VERSION 5.7 ;
BUSBITCHARS "[]" ;
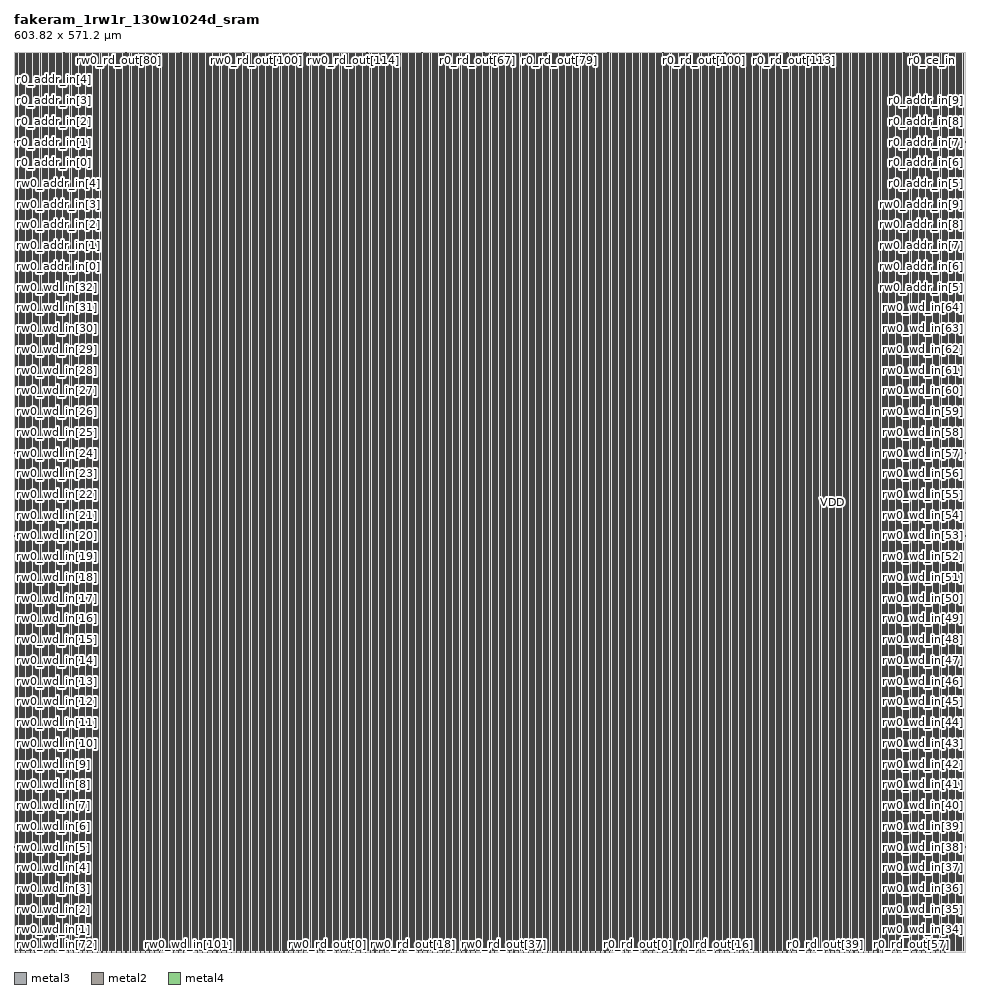
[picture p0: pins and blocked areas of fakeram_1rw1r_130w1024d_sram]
MACRO fakeram_1rw1r_130w1024d_sram
  FOREIGN fakeram_1rw1r_130w1024d_sram 0 0 ;
  SYMMETRY X Y R90 ;
  SIZE 603.820 BY 571.200 ;
  CLASS BLOCK ;
  PIN rw0_wd_in[0]
    DIRECTION INPUT ;
    USE SIGNAL ;
    SHAPE ABUTMENT ;
    PORT
      LAYER metal3 ;
      RECT 0.000 0.805 0.210 0.875 ;
    END
  END rw0_wd_in[0]
  PIN rw0_wd_in[1]
    DIRECTION INPUT ;
    USE SIGNAL ;
    SHAPE ABUTMENT ;
    PORT
      LAYER metal3 ;
      RECT 0.000 13.965 0.210 14.035 ;
    END
  END rw0_wd_in[1]
  PIN rw0_wd_in[2]
    DIRECTION INPUT ;
    USE SIGNAL ;
    SHAPE ABUTMENT ;
    PORT
      LAYER metal3 ;
      RECT 0.000 27.125 0.210 27.195 ;
    END
  END rw0_wd_in[2]
  PIN rw0_wd_in[3]
    DIRECTION INPUT ;
    USE SIGNAL ;
    SHAPE ABUTMENT ;
    PORT
      LAYER metal3 ;
      RECT 0.000 40.285 0.210 40.355 ;
    END
  END rw0_wd_in[3]
  PIN rw0_wd_in[4]
    DIRECTION INPUT ;
    USE SIGNAL ;
    SHAPE ABUTMENT ;
    PORT
      LAYER metal3 ;
      RECT 0.000 53.445 0.210 53.515 ;
    END
  END rw0_wd_in[4]
  PIN rw0_wd_in[5]
    DIRECTION INPUT ;
    USE SIGNAL ;
    SHAPE ABUTMENT ;
    PORT
      LAYER metal3 ;
      RECT 0.000 66.605 0.210 66.675 ;
    END
  END rw0_wd_in[5]
  PIN rw0_wd_in[6]
    DIRECTION INPUT ;
    USE SIGNAL ;
    SHAPE ABUTMENT ;
    PORT
      LAYER metal3 ;
      RECT 0.000 79.765 0.210 79.835 ;
    END
  END rw0_wd_in[6]
  PIN rw0_wd_in[7]
    DIRECTION INPUT ;
    USE SIGNAL ;
    SHAPE ABUTMENT ;
    PORT
      LAYER metal3 ;
      RECT 0.000 92.925 0.210 92.995 ;
    END
  END rw0_wd_in[7]
  PIN rw0_wd_in[8]
    DIRECTION INPUT ;
    USE SIGNAL ;
    SHAPE ABUTMENT ;
    PORT
      LAYER metal3 ;
      RECT 0.000 106.085 0.210 106.155 ;
    END
  END rw0_wd_in[8]
  PIN rw0_wd_in[9]
    DIRECTION INPUT ;
    USE SIGNAL ;
    SHAPE ABUTMENT ;
    PORT
      LAYER metal3 ;
      RECT 0.000 119.245 0.210 119.315 ;
    END
  END rw0_wd_in[9]
  PIN rw0_wd_in[10]
    DIRECTION INPUT ;
    USE SIGNAL ;
    SHAPE ABUTMENT ;
    PORT
      LAYER metal3 ;
      RECT 0.000 132.405 0.210 132.475 ;
    END
  END rw0_wd_in[10]
  PIN rw0_wd_in[11]
    DIRECTION INPUT ;
    USE SIGNAL ;
    SHAPE ABUTMENT ;
    PORT
      LAYER metal3 ;
      RECT 0.000 145.565 0.210 145.635 ;
    END
  END rw0_wd_in[11]
  PIN rw0_wd_in[12]
    DIRECTION INPUT ;
    USE SIGNAL ;
    SHAPE ABUTMENT ;
    PORT
      LAYER metal3 ;
      RECT 0.000 158.725 0.210 158.795 ;
    END
  END rw0_wd_in[12]
  PIN rw0_wd_in[13]
    DIRECTION INPUT ;
    USE SIGNAL ;
    SHAPE ABUTMENT ;
    PORT
      LAYER metal3 ;
      RECT 0.000 171.885 0.210 171.955 ;
    END
  END rw0_wd_in[13]
  PIN rw0_wd_in[14]
    DIRECTION INPUT ;
    USE SIGNAL ;
    SHAPE ABUTMENT ;
    PORT
      LAYER metal3 ;
      RECT 0.000 185.045 0.210 185.115 ;
    END
  END rw0_wd_in[14]
  PIN rw0_wd_in[15]
    DIRECTION INPUT ;
    USE SIGNAL ;
    SHAPE ABUTMENT ;
    PORT
      LAYER metal3 ;
      RECT 0.000 198.205 0.210 198.275 ;
    END
  END rw0_wd_in[15]
  PIN rw0_wd_in[16]
    DIRECTION INPUT ;
    USE SIGNAL ;
    SHAPE ABUTMENT ;
    PORT
      LAYER metal3 ;
      RECT 0.000 211.365 0.210 211.435 ;
    END
  END rw0_wd_in[16]
  PIN rw0_wd_in[17]
    DIRECTION INPUT ;
    USE SIGNAL ;
    SHAPE ABUTMENT ;
    PORT
      LAYER metal3 ;
      RECT 0.000 224.525 0.210 224.595 ;
    END
  END rw0_wd_in[17]
  PIN rw0_wd_in[18]
    DIRECTION INPUT ;
    USE SIGNAL ;
    SHAPE ABUTMENT ;
    PORT
      LAYER metal3 ;
      RECT 0.000 237.685 0.210 237.755 ;
    END
  END rw0_wd_in[18]
  PIN rw0_wd_in[19]
    DIRECTION INPUT ;
    USE SIGNAL ;
    SHAPE ABUTMENT ;
    PORT
      LAYER metal3 ;
      RECT 0.000 250.845 0.210 250.915 ;
    END
  END rw0_wd_in[19]
  PIN rw0_wd_in[20]
    DIRECTION INPUT ;
    USE SIGNAL ;
    SHAPE ABUTMENT ;
    PORT
      LAYER metal3 ;
      RECT 0.000 264.005 0.210 264.075 ;
    END
  END rw0_wd_in[20]
  PIN rw0_wd_in[21]
    DIRECTION INPUT ;
    USE SIGNAL ;
    SHAPE ABUTMENT ;
    PORT
      LAYER metal3 ;
      RECT 0.000 277.165 0.210 277.235 ;
    END
  END rw0_wd_in[21]
  PIN rw0_wd_in[22]
    DIRECTION INPUT ;
    USE SIGNAL ;
    SHAPE ABUTMENT ;
    PORT
      LAYER metal3 ;
      RECT 0.000 290.325 0.210 290.395 ;
    END
  END rw0_wd_in[22]
  PIN rw0_wd_in[23]
    DIRECTION INPUT ;
    USE SIGNAL ;
    SHAPE ABUTMENT ;
    PORT
      LAYER metal3 ;
      RECT 0.000 303.485 0.210 303.555 ;
    END
  END rw0_wd_in[23]
  PIN rw0_wd_in[24]
    DIRECTION INPUT ;
    USE SIGNAL ;
    SHAPE ABUTMENT ;
    PORT
      LAYER metal3 ;
      RECT 0.000 316.645 0.210 316.715 ;
    END
  END rw0_wd_in[24]
  PIN rw0_wd_in[25]
    DIRECTION INPUT ;
    USE SIGNAL ;
    SHAPE ABUTMENT ;
    PORT
      LAYER metal3 ;
      RECT 0.000 329.805 0.210 329.875 ;
    END
  END rw0_wd_in[25]
  PIN rw0_wd_in[26]
    DIRECTION INPUT ;
    USE SIGNAL ;
    SHAPE ABUTMENT ;
    PORT
      LAYER metal3 ;
      RECT 0.000 342.965 0.210 343.035 ;
    END
  END rw0_wd_in[26]
  PIN rw0_wd_in[27]
    DIRECTION INPUT ;
    USE SIGNAL ;
    SHAPE ABUTMENT ;
    PORT
      LAYER metal3 ;
      RECT 0.000 356.125 0.210 356.195 ;
    END
  END rw0_wd_in[27]
  PIN rw0_wd_in[28]
    DIRECTION INPUT ;
    USE SIGNAL ;
    SHAPE ABUTMENT ;
    PORT
      LAYER metal3 ;
      RECT 0.000 369.285 0.210 369.355 ;
    END
  END rw0_wd_in[28]
  PIN rw0_wd_in[29]
    DIRECTION INPUT ;
    USE SIGNAL ;
    SHAPE ABUTMENT ;
    PORT
      LAYER metal3 ;
      RECT 0.000 382.445 0.210 382.515 ;
    END
  END rw0_wd_in[29]
  PIN rw0_wd_in[30]
    DIRECTION INPUT ;
    USE SIGNAL ;
    SHAPE ABUTMENT ;
    PORT
      LAYER metal3 ;
      RECT 0.000 395.605 0.210 395.675 ;
    END
  END rw0_wd_in[30]
  PIN rw0_wd_in[31]
    DIRECTION INPUT ;
    USE SIGNAL ;
    SHAPE ABUTMENT ;
    PORT
      LAYER metal3 ;
      RECT 0.000 408.765 0.210 408.835 ;
    END
  END rw0_wd_in[31]
  PIN rw0_wd_in[32]
    DIRECTION INPUT ;
    USE SIGNAL ;
    SHAPE ABUTMENT ;
    PORT
      LAYER metal3 ;
      RECT 0.000 421.925 0.210 421.995 ;
    END
  END rw0_wd_in[32]
  PIN rw0_wd_in[33]
    DIRECTION INPUT ;
    USE SIGNAL ;
    SHAPE ABUTMENT ;
    PORT
      LAYER metal3 ;
      RECT 603.610 0.805 603.820 0.875 ;
    END
  END rw0_wd_in[33]
  PIN rw0_wd_in[34]
    DIRECTION INPUT ;
    USE SIGNAL ;
    SHAPE ABUTMENT ;
    PORT
      LAYER metal3 ;
      RECT 603.610 13.965 603.820 14.035 ;
    END
  END rw0_wd_in[34]
  PIN rw0_wd_in[35]
    DIRECTION INPUT ;
    USE SIGNAL ;
    SHAPE ABUTMENT ;
    PORT
      LAYER metal3 ;
      RECT 603.610 27.125 603.820 27.195 ;
    END
  END rw0_wd_in[35]
  PIN rw0_wd_in[36]
    DIRECTION INPUT ;
    USE SIGNAL ;
    SHAPE ABUTMENT ;
    PORT
      LAYER metal3 ;
      RECT 603.610 40.285 603.820 40.355 ;
    END
  END rw0_wd_in[36]
  PIN rw0_wd_in[37]
    DIRECTION INPUT ;
    USE SIGNAL ;
    SHAPE ABUTMENT ;
    PORT
      LAYER metal3 ;
      RECT 603.610 53.445 603.820 53.515 ;
    END
  END rw0_wd_in[37]
  PIN rw0_wd_in[38]
    DIRECTION INPUT ;
    USE SIGNAL ;
    SHAPE ABUTMENT ;
    PORT
      LAYER metal3 ;
      RECT 603.610 66.605 603.820 66.675 ;
    END
  END rw0_wd_in[38]
  PIN rw0_wd_in[39]
    DIRECTION INPUT ;
    USE SIGNAL ;
    SHAPE ABUTMENT ;
    PORT
      LAYER metal3 ;
      RECT 603.610 79.765 603.820 79.835 ;
    END
  END rw0_wd_in[39]
  PIN rw0_wd_in[40]
    DIRECTION INPUT ;
    USE SIGNAL ;
    SHAPE ABUTMENT ;
    PORT
      LAYER metal3 ;
      RECT 603.610 92.925 603.820 92.995 ;
    END
  END rw0_wd_in[40]
  PIN rw0_wd_in[41]
    DIRECTION INPUT ;
    USE SIGNAL ;
    SHAPE ABUTMENT ;
    PORT
      LAYER metal3 ;
      RECT 603.610 106.085 603.820 106.155 ;
    END
  END rw0_wd_in[41]
  PIN rw0_wd_in[42]
    DIRECTION INPUT ;
    USE SIGNAL ;
    SHAPE ABUTMENT ;
    PORT
      LAYER metal3 ;
      RECT 603.610 119.245 603.820 119.315 ;
    END
  END rw0_wd_in[42]
  PIN rw0_wd_in[43]
    DIRECTION INPUT ;
    USE SIGNAL ;
    SHAPE ABUTMENT ;
    PORT
      LAYER metal3 ;
      RECT 603.610 132.405 603.820 132.475 ;
    END
  END rw0_wd_in[43]
  PIN rw0_wd_in[44]
    DIRECTION INPUT ;
    USE SIGNAL ;
    SHAPE ABUTMENT ;
    PORT
      LAYER metal3 ;
      RECT 603.610 145.565 603.820 145.635 ;
    END
  END rw0_wd_in[44]
  PIN rw0_wd_in[45]
    DIRECTION INPUT ;
    USE SIGNAL ;
    SHAPE ABUTMENT ;
    PORT
      LAYER metal3 ;
      RECT 603.610 158.725 603.820 158.795 ;
    END
  END rw0_wd_in[45]
  PIN rw0_wd_in[46]
    DIRECTION INPUT ;
    USE SIGNAL ;
    SHAPE ABUTMENT ;
    PORT
      LAYER metal3 ;
      RECT 603.610 171.885 603.820 171.955 ;
    END
  END rw0_wd_in[46]
  PIN rw0_wd_in[47]
    DIRECTION INPUT ;
    USE SIGNAL ;
    SHAPE ABUTMENT ;
    PORT
      LAYER metal3 ;
      RECT 603.610 185.045 603.820 185.115 ;
    END
  END rw0_wd_in[47]
  PIN rw0_wd_in[48]
    DIRECTION INPUT ;
    USE SIGNAL ;
    SHAPE ABUTMENT ;
    PORT
      LAYER metal3 ;
      RECT 603.610 198.205 603.820 198.275 ;
    END
  END rw0_wd_in[48]
  PIN rw0_wd_in[49]
    DIRECTION INPUT ;
    USE SIGNAL ;
    SHAPE ABUTMENT ;
    PORT
      LAYER metal3 ;
      RECT 603.610 211.365 603.820 211.435 ;
    END
  END rw0_wd_in[49]
  PIN rw0_wd_in[50]
    DIRECTION INPUT ;
    USE SIGNAL ;
    SHAPE ABUTMENT ;
    PORT
      LAYER metal3 ;
      RECT 603.610 224.525 603.820 224.595 ;
    END
  END rw0_wd_in[50]
  PIN rw0_wd_in[51]
    DIRECTION INPUT ;
    USE SIGNAL ;
    SHAPE ABUTMENT ;
    PORT
      LAYER metal3 ;
      RECT 603.610 237.685 603.820 237.755 ;
    END
  END rw0_wd_in[51]
  PIN rw0_wd_in[52]
    DIRECTION INPUT ;
    USE SIGNAL ;
    SHAPE ABUTMENT ;
    PORT
      LAYER metal3 ;
      RECT 603.610 250.845 603.820 250.915 ;
    END
  END rw0_wd_in[52]
  PIN rw0_wd_in[53]
    DIRECTION INPUT ;
    USE SIGNAL ;
    SHAPE ABUTMENT ;
    PORT
      LAYER metal3 ;
      RECT 603.610 264.005 603.820 264.075 ;
    END
  END rw0_wd_in[53]
  PIN rw0_wd_in[54]
    DIRECTION INPUT ;
    USE SIGNAL ;
    SHAPE ABUTMENT ;
    PORT
      LAYER metal3 ;
      RECT 603.610 277.165 603.820 277.235 ;
    END
  END rw0_wd_in[54]
  PIN rw0_wd_in[55]
    DIRECTION INPUT ;
    USE SIGNAL ;
    SHAPE ABUTMENT ;
    PORT
      LAYER metal3 ;
      RECT 603.610 290.325 603.820 290.395 ;
    END
  END rw0_wd_in[55]
  PIN rw0_wd_in[56]
    DIRECTION INPUT ;
    USE SIGNAL ;
    SHAPE ABUTMENT ;
    PORT
      LAYER metal3 ;
      RECT 603.610 303.485 603.820 303.555 ;
    END
  END rw0_wd_in[56]
  PIN rw0_wd_in[57]
    DIRECTION INPUT ;
    USE SIGNAL ;
    SHAPE ABUTMENT ;
    PORT
      LAYER metal3 ;
      RECT 603.610 316.645 603.820 316.715 ;
    END
  END rw0_wd_in[57]
  PIN rw0_wd_in[58]
    DIRECTION INPUT ;
    USE SIGNAL ;
    SHAPE ABUTMENT ;
    PORT
      LAYER metal3 ;
      RECT 603.610 329.805 603.820 329.875 ;
    END
  END rw0_wd_in[58]
  PIN rw0_wd_in[59]
    DIRECTION INPUT ;
    USE SIGNAL ;
    SHAPE ABUTMENT ;
    PORT
      LAYER metal3 ;
      RECT 603.610 342.965 603.820 343.035 ;
    END
  END rw0_wd_in[59]
  PIN rw0_wd_in[60]
    DIRECTION INPUT ;
    USE SIGNAL ;
    SHAPE ABUTMENT ;
    PORT
      LAYER metal3 ;
      RECT 603.610 356.125 603.820 356.195 ;
    END
  END rw0_wd_in[60]
  PIN rw0_wd_in[61]
    DIRECTION INPUT ;
    USE SIGNAL ;
    SHAPE ABUTMENT ;
    PORT
      LAYER metal3 ;
      RECT 603.610 369.285 603.820 369.355 ;
    END
  END rw0_wd_in[61]
  PIN rw0_wd_in[62]
    DIRECTION INPUT ;
    USE SIGNAL ;
    SHAPE ABUTMENT ;
    PORT
      LAYER metal3 ;
      RECT 603.610 382.445 603.820 382.515 ;
    END
  END rw0_wd_in[62]
  PIN rw0_wd_in[63]
    DIRECTION INPUT ;
    USE SIGNAL ;
    SHAPE ABUTMENT ;
    PORT
      LAYER metal3 ;
      RECT 603.610 395.605 603.820 395.675 ;
    END
  END rw0_wd_in[63]
  PIN rw0_wd_in[64]
    DIRECTION INPUT ;
    USE SIGNAL ;
    SHAPE ABUTMENT ;
    PORT
      LAYER metal3 ;
      RECT 603.610 408.765 603.820 408.835 ;
    END
  END rw0_wd_in[64]
  PIN rw0_wd_in[65]
    DIRECTION INPUT ;
    USE SIGNAL ;
    SHAPE ABUTMENT ;
    PORT
      LAYER metal2 ;
      RECT 1.105 0.000 1.175 0.210 ;
    END
  END rw0_wd_in[65]
  PIN rw0_wd_in[66]
    DIRECTION INPUT ;
    USE SIGNAL ;
    SHAPE ABUTMENT ;
    PORT
      LAYER metal2 ;
      RECT 4.145 0.000 4.215 0.210 ;
    END
  END rw0_wd_in[66]
  PIN rw0_wd_in[67]
    DIRECTION INPUT ;
    USE SIGNAL ;
    SHAPE ABUTMENT ;
    PORT
      LAYER metal2 ;
      RECT 7.185 0.000 7.255 0.210 ;
    END
  END rw0_wd_in[67]
  PIN rw0_wd_in[68]
    DIRECTION INPUT ;
    USE SIGNAL ;
    SHAPE ABUTMENT ;
    PORT
      LAYER metal2 ;
      RECT 10.225 0.000 10.295 0.210 ;
    END
  END rw0_wd_in[68]
  PIN rw0_wd_in[69]
    DIRECTION INPUT ;
    USE SIGNAL ;
    SHAPE ABUTMENT ;
    PORT
      LAYER metal2 ;
      RECT 13.265 0.000 13.335 0.210 ;
    END
  END rw0_wd_in[69]
  PIN rw0_wd_in[70]
    DIRECTION INPUT ;
    USE SIGNAL ;
    SHAPE ABUTMENT ;
    PORT
      LAYER metal2 ;
      RECT 16.305 0.000 16.375 0.210 ;
    END
  END rw0_wd_in[70]
  PIN rw0_wd_in[71]
    DIRECTION INPUT ;
    USE SIGNAL ;
    SHAPE ABUTMENT ;
    PORT
      LAYER metal2 ;
      RECT 19.345 0.000 19.415 0.210 ;
    END
  END rw0_wd_in[71]
  PIN rw0_wd_in[72]
    DIRECTION INPUT ;
    USE SIGNAL ;
    SHAPE ABUTMENT ;
    PORT
      LAYER metal2 ;
      RECT 22.385 0.000 22.455 0.210 ;
    END
  END rw0_wd_in[72]
  PIN rw0_wd_in[73]
    DIRECTION INPUT ;
    USE SIGNAL ;
    SHAPE ABUTMENT ;
    PORT
      LAYER metal2 ;
      RECT 25.425 0.000 25.495 0.210 ;
    END
  END rw0_wd_in[73]
  PIN rw0_wd_in[74]
    DIRECTION INPUT ;
    USE SIGNAL ;
    SHAPE ABUTMENT ;
    PORT
      LAYER metal2 ;
      RECT 28.465 0.000 28.535 0.210 ;
    END
  END rw0_wd_in[74]
  PIN rw0_wd_in[75]
    DIRECTION INPUT ;
    USE SIGNAL ;
    SHAPE ABUTMENT ;
    PORT
      LAYER metal2 ;
      RECT 31.505 0.000 31.575 0.210 ;
    END
  END rw0_wd_in[75]
  PIN rw0_wd_in[76]
    DIRECTION INPUT ;
    USE SIGNAL ;
    SHAPE ABUTMENT ;
    PORT
      LAYER metal2 ;
      RECT 34.545 0.000 34.615 0.210 ;
    END
  END rw0_wd_in[76]
  PIN rw0_wd_in[77]
    DIRECTION INPUT ;
    USE SIGNAL ;
    SHAPE ABUTMENT ;
    PORT
      LAYER metal2 ;
      RECT 37.585 0.000 37.655 0.210 ;
    END
  END rw0_wd_in[77]
  PIN rw0_wd_in[78]
    DIRECTION INPUT ;
    USE SIGNAL ;
    SHAPE ABUTMENT ;
    PORT
      LAYER metal2 ;
      RECT 40.625 0.000 40.695 0.210 ;
    END
  END rw0_wd_in[78]
  PIN rw0_wd_in[79]
    DIRECTION INPUT ;
    USE SIGNAL ;
    SHAPE ABUTMENT ;
    PORT
      LAYER metal2 ;
      RECT 43.665 0.000 43.735 0.210 ;
    END
  END rw0_wd_in[79]
  PIN rw0_wd_in[80]
    DIRECTION INPUT ;
    USE SIGNAL ;
    SHAPE ABUTMENT ;
    PORT
      LAYER metal2 ;
      RECT 46.705 0.000 46.775 0.210 ;
    END
  END rw0_wd_in[80]
  PIN rw0_wd_in[81]
    DIRECTION INPUT ;
    USE SIGNAL ;
    SHAPE ABUTMENT ;
    PORT
      LAYER metal2 ;
      RECT 49.745 0.000 49.815 0.210 ;
    END
  END rw0_wd_in[81]
  PIN rw0_wd_in[82]
    DIRECTION INPUT ;
    USE SIGNAL ;
    SHAPE ABUTMENT ;
    PORT
      LAYER metal2 ;
      RECT 52.785 0.000 52.855 0.210 ;
    END
  END rw0_wd_in[82]
  PIN rw0_wd_in[83]
    DIRECTION INPUT ;
    USE SIGNAL ;
    SHAPE ABUTMENT ;
    PORT
      LAYER metal2 ;
      RECT 55.825 0.000 55.895 0.210 ;
    END
  END rw0_wd_in[83]
  PIN rw0_wd_in[84]
    DIRECTION INPUT ;
    USE SIGNAL ;
    SHAPE ABUTMENT ;
    PORT
      LAYER metal2 ;
      RECT 58.865 0.000 58.935 0.210 ;
    END
  END rw0_wd_in[84]
  PIN rw0_wd_in[85]
    DIRECTION INPUT ;
    USE SIGNAL ;
    SHAPE ABUTMENT ;
    PORT
      LAYER metal2 ;
      RECT 61.905 0.000 61.975 0.210 ;
    END
  END rw0_wd_in[85]
  PIN rw0_wd_in[86]
    DIRECTION INPUT ;
    USE SIGNAL ;
    SHAPE ABUTMENT ;
    PORT
      LAYER metal2 ;
      RECT 64.945 0.000 65.015 0.210 ;
    END
  END rw0_wd_in[86]
  PIN rw0_wd_in[87]
    DIRECTION INPUT ;
    USE SIGNAL ;
    SHAPE ABUTMENT ;
    PORT
      LAYER metal2 ;
      RECT 67.985 0.000 68.055 0.210 ;
    END
  END rw0_wd_in[87]
  PIN rw0_wd_in[88]
    DIRECTION INPUT ;
    USE SIGNAL ;
    SHAPE ABUTMENT ;
    PORT
      LAYER metal2 ;
      RECT 71.025 0.000 71.095 0.210 ;
    END
  END rw0_wd_in[88]
  PIN rw0_wd_in[89]
    DIRECTION INPUT ;
    USE SIGNAL ;
    SHAPE ABUTMENT ;
    PORT
      LAYER metal2 ;
      RECT 74.065 0.000 74.135 0.210 ;
    END
  END rw0_wd_in[89]
  PIN rw0_wd_in[90]
    DIRECTION INPUT ;
    USE SIGNAL ;
    SHAPE ABUTMENT ;
    PORT
      LAYER metal2 ;
      RECT 77.105 0.000 77.175 0.210 ;
    END
  END rw0_wd_in[90]
  PIN rw0_wd_in[91]
    DIRECTION INPUT ;
    USE SIGNAL ;
    SHAPE ABUTMENT ;
    PORT
      LAYER metal2 ;
      RECT 80.145 0.000 80.215 0.210 ;
    END
  END rw0_wd_in[91]
  PIN rw0_wd_in[92]
    DIRECTION INPUT ;
    USE SIGNAL ;
    SHAPE ABUTMENT ;
    PORT
      LAYER metal2 ;
      RECT 83.185 0.000 83.255 0.210 ;
    END
  END rw0_wd_in[92]
  PIN rw0_wd_in[93]
    DIRECTION INPUT ;
    USE SIGNAL ;
    SHAPE ABUTMENT ;
    PORT
      LAYER metal2 ;
      RECT 86.225 0.000 86.295 0.210 ;
    END
  END rw0_wd_in[93]
  PIN rw0_wd_in[94]
    DIRECTION INPUT ;
    USE SIGNAL ;
    SHAPE ABUTMENT ;
    PORT
      LAYER metal2 ;
      RECT 89.265 0.000 89.335 0.210 ;
    END
  END rw0_wd_in[94]
  PIN rw0_wd_in[95]
    DIRECTION INPUT ;
    USE SIGNAL ;
    SHAPE ABUTMENT ;
    PORT
      LAYER metal2 ;
      RECT 92.305 0.000 92.375 0.210 ;
    END
  END rw0_wd_in[95]
  PIN rw0_wd_in[96]
    DIRECTION INPUT ;
    USE SIGNAL ;
    SHAPE ABUTMENT ;
    PORT
      LAYER metal2 ;
      RECT 95.345 0.000 95.415 0.210 ;
    END
  END rw0_wd_in[96]
  PIN rw0_wd_in[97]
    DIRECTION INPUT ;
    USE SIGNAL ;
    SHAPE ABUTMENT ;
    PORT
      LAYER metal2 ;
      RECT 98.385 0.000 98.455 0.210 ;
    END
  END rw0_wd_in[97]
  PIN rw0_wd_in[98]
    DIRECTION INPUT ;
    USE SIGNAL ;
    SHAPE ABUTMENT ;
    PORT
      LAYER metal2 ;
      RECT 101.425 0.000 101.495 0.210 ;
    END
  END rw0_wd_in[98]
  PIN rw0_wd_in[99]
    DIRECTION INPUT ;
    USE SIGNAL ;
    SHAPE ABUTMENT ;
    PORT
      LAYER metal2 ;
      RECT 104.465 0.000 104.535 0.210 ;
    END
  END rw0_wd_in[99]
  PIN rw0_wd_in[100]
    DIRECTION INPUT ;
    USE SIGNAL ;
    SHAPE ABUTMENT ;
    PORT
      LAYER metal2 ;
      RECT 107.505 0.000 107.575 0.210 ;
    END
  END rw0_wd_in[100]
  PIN rw0_wd_in[101]
    DIRECTION INPUT ;
    USE SIGNAL ;
    SHAPE ABUTMENT ;
    PORT
      LAYER metal2 ;
      RECT 110.545 0.000 110.615 0.210 ;
    END
  END rw0_wd_in[101]
  PIN rw0_wd_in[102]
    DIRECTION INPUT ;
    USE SIGNAL ;
    SHAPE ABUTMENT ;
    PORT
      LAYER metal2 ;
      RECT 113.585 0.000 113.655 0.210 ;
    END
  END rw0_wd_in[102]
  PIN rw0_wd_in[103]
    DIRECTION INPUT ;
    USE SIGNAL ;
    SHAPE ABUTMENT ;
    PORT
      LAYER metal2 ;
      RECT 116.625 0.000 116.695 0.210 ;
    END
  END rw0_wd_in[103]
  PIN rw0_wd_in[104]
    DIRECTION INPUT ;
    USE SIGNAL ;
    SHAPE ABUTMENT ;
    PORT
      LAYER metal2 ;
      RECT 119.665 0.000 119.735 0.210 ;
    END
  END rw0_wd_in[104]
  PIN rw0_wd_in[105]
    DIRECTION INPUT ;
    USE SIGNAL ;
    SHAPE ABUTMENT ;
    PORT
      LAYER metal2 ;
      RECT 122.705 0.000 122.775 0.210 ;
    END
  END rw0_wd_in[105]
  PIN rw0_wd_in[106]
    DIRECTION INPUT ;
    USE SIGNAL ;
    SHAPE ABUTMENT ;
    PORT
      LAYER metal2 ;
      RECT 125.745 0.000 125.815 0.210 ;
    END
  END rw0_wd_in[106]
  PIN rw0_wd_in[107]
    DIRECTION INPUT ;
    USE SIGNAL ;
    SHAPE ABUTMENT ;
    PORT
      LAYER metal2 ;
      RECT 128.785 0.000 128.855 0.210 ;
    END
  END rw0_wd_in[107]
  PIN rw0_wd_in[108]
    DIRECTION INPUT ;
    USE SIGNAL ;
    SHAPE ABUTMENT ;
    PORT
      LAYER metal2 ;
      RECT 131.825 0.000 131.895 0.210 ;
    END
  END rw0_wd_in[108]
  PIN rw0_wd_in[109]
    DIRECTION INPUT ;
    USE SIGNAL ;
    SHAPE ABUTMENT ;
    PORT
      LAYER metal2 ;
      RECT 134.865 0.000 134.935 0.210 ;
    END
  END rw0_wd_in[109]
  PIN rw0_wd_in[110]
    DIRECTION INPUT ;
    USE SIGNAL ;
    SHAPE ABUTMENT ;
    PORT
      LAYER metal2 ;
      RECT 137.905 0.000 137.975 0.210 ;
    END
  END rw0_wd_in[110]
  PIN rw0_wd_in[111]
    DIRECTION INPUT ;
    USE SIGNAL ;
    SHAPE ABUTMENT ;
    PORT
      LAYER metal2 ;
      RECT 140.945 0.000 141.015 0.210 ;
    END
  END rw0_wd_in[111]
  PIN rw0_wd_in[112]
    DIRECTION INPUT ;
    USE SIGNAL ;
    SHAPE ABUTMENT ;
    PORT
      LAYER metal2 ;
      RECT 143.985 0.000 144.055 0.210 ;
    END
  END rw0_wd_in[112]
  PIN rw0_wd_in[113]
    DIRECTION INPUT ;
    USE SIGNAL ;
    SHAPE ABUTMENT ;
    PORT
      LAYER metal2 ;
      RECT 147.025 0.000 147.095 0.210 ;
    END
  END rw0_wd_in[113]
  PIN rw0_wd_in[114]
    DIRECTION INPUT ;
    USE SIGNAL ;
    SHAPE ABUTMENT ;
    PORT
      LAYER metal2 ;
      RECT 150.065 0.000 150.135 0.210 ;
    END
  END rw0_wd_in[114]
  PIN rw0_wd_in[115]
    DIRECTION INPUT ;
    USE SIGNAL ;
    SHAPE ABUTMENT ;
    PORT
      LAYER metal2 ;
      RECT 153.105 0.000 153.175 0.210 ;
    END
  END rw0_wd_in[115]
  PIN rw0_wd_in[116]
    DIRECTION INPUT ;
    USE SIGNAL ;
    SHAPE ABUTMENT ;
    PORT
      LAYER metal2 ;
      RECT 156.145 0.000 156.215 0.210 ;
    END
  END rw0_wd_in[116]
  PIN rw0_wd_in[117]
    DIRECTION INPUT ;
    USE SIGNAL ;
    SHAPE ABUTMENT ;
    PORT
      LAYER metal2 ;
      RECT 159.185 0.000 159.255 0.210 ;
    END
  END rw0_wd_in[117]
  PIN rw0_wd_in[118]
    DIRECTION INPUT ;
    USE SIGNAL ;
    SHAPE ABUTMENT ;
    PORT
      LAYER metal2 ;
      RECT 162.225 0.000 162.295 0.210 ;
    END
  END rw0_wd_in[118]
  PIN rw0_wd_in[119]
    DIRECTION INPUT ;
    USE SIGNAL ;
    SHAPE ABUTMENT ;
    PORT
      LAYER metal2 ;
      RECT 165.265 0.000 165.335 0.210 ;
    END
  END rw0_wd_in[119]
  PIN rw0_wd_in[120]
    DIRECTION INPUT ;
    USE SIGNAL ;
    SHAPE ABUTMENT ;
    PORT
      LAYER metal2 ;
      RECT 168.305 0.000 168.375 0.210 ;
    END
  END rw0_wd_in[120]
  PIN rw0_wd_in[121]
    DIRECTION INPUT ;
    USE SIGNAL ;
    SHAPE ABUTMENT ;
    PORT
      LAYER metal2 ;
      RECT 171.345 0.000 171.415 0.210 ;
    END
  END rw0_wd_in[121]
  PIN rw0_wd_in[122]
    DIRECTION INPUT ;
    USE SIGNAL ;
    SHAPE ABUTMENT ;
    PORT
      LAYER metal2 ;
      RECT 174.385 0.000 174.455 0.210 ;
    END
  END rw0_wd_in[122]
  PIN rw0_wd_in[123]
    DIRECTION INPUT ;
    USE SIGNAL ;
    SHAPE ABUTMENT ;
    PORT
      LAYER metal2 ;
      RECT 177.425 0.000 177.495 0.210 ;
    END
  END rw0_wd_in[123]
  PIN rw0_wd_in[124]
    DIRECTION INPUT ;
    USE SIGNAL ;
    SHAPE ABUTMENT ;
    PORT
      LAYER metal2 ;
      RECT 180.465 0.000 180.535 0.210 ;
    END
  END rw0_wd_in[124]
  PIN rw0_wd_in[125]
    DIRECTION INPUT ;
    USE SIGNAL ;
    SHAPE ABUTMENT ;
    PORT
      LAYER metal2 ;
      RECT 183.505 0.000 183.575 0.210 ;
    END
  END rw0_wd_in[125]
  PIN rw0_wd_in[126]
    DIRECTION INPUT ;
    USE SIGNAL ;
    SHAPE ABUTMENT ;
    PORT
      LAYER metal2 ;
      RECT 186.545 0.000 186.615 0.210 ;
    END
  END rw0_wd_in[126]
  PIN rw0_wd_in[127]
    DIRECTION INPUT ;
    USE SIGNAL ;
    SHAPE ABUTMENT ;
    PORT
      LAYER metal2 ;
      RECT 189.585 0.000 189.655 0.210 ;
    END
  END rw0_wd_in[127]
  PIN rw0_wd_in[128]
    DIRECTION INPUT ;
    USE SIGNAL ;
    SHAPE ABUTMENT ;
    PORT
      LAYER metal2 ;
      RECT 192.625 0.000 192.695 0.210 ;
    END
  END rw0_wd_in[128]
  PIN rw0_wd_in[129]
    DIRECTION INPUT ;
    USE SIGNAL ;
    SHAPE ABUTMENT ;
    PORT
      LAYER metal2 ;
      RECT 195.665 0.000 195.735 0.210 ;
    END
  END rw0_wd_in[129]
  PIN rw0_rd_out[0]
    DIRECTION OUTPUT ;
    USE SIGNAL ;
    SHAPE ABUTMENT ;
    PORT
      LAYER metal2 ;
      RECT 198.705 0.000 198.775 0.210 ;
    END
  END rw0_rd_out[0]
  PIN rw0_rd_out[1]
    DIRECTION OUTPUT ;
    USE SIGNAL ;
    SHAPE ABUTMENT ;
    PORT
      LAYER metal2 ;
      RECT 201.745 0.000 201.815 0.210 ;
    END
  END rw0_rd_out[1]
  PIN rw0_rd_out[2]
    DIRECTION OUTPUT ;
    USE SIGNAL ;
    SHAPE ABUTMENT ;
    PORT
      LAYER metal2 ;
      RECT 204.785 0.000 204.855 0.210 ;
    END
  END rw0_rd_out[2]
  PIN rw0_rd_out[3]
    DIRECTION OUTPUT ;
    USE SIGNAL ;
    SHAPE ABUTMENT ;
    PORT
      LAYER metal2 ;
      RECT 207.825 0.000 207.895 0.210 ;
    END
  END rw0_rd_out[3]
  PIN rw0_rd_out[4]
    DIRECTION OUTPUT ;
    USE SIGNAL ;
    SHAPE ABUTMENT ;
    PORT
      LAYER metal2 ;
      RECT 210.865 0.000 210.935 0.210 ;
    END
  END rw0_rd_out[4]
  PIN rw0_rd_out[5]
    DIRECTION OUTPUT ;
    USE SIGNAL ;
    SHAPE ABUTMENT ;
    PORT
      LAYER metal2 ;
      RECT 213.905 0.000 213.975 0.210 ;
    END
  END rw0_rd_out[5]
  PIN rw0_rd_out[6]
    DIRECTION OUTPUT ;
    USE SIGNAL ;
    SHAPE ABUTMENT ;
    PORT
      LAYER metal2 ;
      RECT 216.945 0.000 217.015 0.210 ;
    END
  END rw0_rd_out[6]
  PIN rw0_rd_out[7]
    DIRECTION OUTPUT ;
    USE SIGNAL ;
    SHAPE ABUTMENT ;
    PORT
      LAYER metal2 ;
      RECT 219.985 0.000 220.055 0.210 ;
    END
  END rw0_rd_out[7]
  PIN rw0_rd_out[8]
    DIRECTION OUTPUT ;
    USE SIGNAL ;
    SHAPE ABUTMENT ;
    PORT
      LAYER metal2 ;
      RECT 223.025 0.000 223.095 0.210 ;
    END
  END rw0_rd_out[8]
  PIN rw0_rd_out[9]
    DIRECTION OUTPUT ;
    USE SIGNAL ;
    SHAPE ABUTMENT ;
    PORT
      LAYER metal2 ;
      RECT 226.065 0.000 226.135 0.210 ;
    END
  END rw0_rd_out[9]
  PIN rw0_rd_out[10]
    DIRECTION OUTPUT ;
    USE SIGNAL ;
    SHAPE ABUTMENT ;
    PORT
      LAYER metal2 ;
      RECT 229.105 0.000 229.175 0.210 ;
    END
  END rw0_rd_out[10]
  PIN rw0_rd_out[11]
    DIRECTION OUTPUT ;
    USE SIGNAL ;
    SHAPE ABUTMENT ;
    PORT
      LAYER metal2 ;
      RECT 232.145 0.000 232.215 0.210 ;
    END
  END rw0_rd_out[11]
  PIN rw0_rd_out[12]
    DIRECTION OUTPUT ;
    USE SIGNAL ;
    SHAPE ABUTMENT ;
    PORT
      LAYER metal2 ;
      RECT 235.185 0.000 235.255 0.210 ;
    END
  END rw0_rd_out[12]
  PIN rw0_rd_out[13]
    DIRECTION OUTPUT ;
    USE SIGNAL ;
    SHAPE ABUTMENT ;
    PORT
      LAYER metal2 ;
      RECT 238.225 0.000 238.295 0.210 ;
    END
  END rw0_rd_out[13]
  PIN rw0_rd_out[14]
    DIRECTION OUTPUT ;
    USE SIGNAL ;
    SHAPE ABUTMENT ;
    PORT
      LAYER metal2 ;
      RECT 241.265 0.000 241.335 0.210 ;
    END
  END rw0_rd_out[14]
  PIN rw0_rd_out[15]
    DIRECTION OUTPUT ;
    USE SIGNAL ;
    SHAPE ABUTMENT ;
    PORT
      LAYER metal2 ;
      RECT 244.305 0.000 244.375 0.210 ;
    END
  END rw0_rd_out[15]
  PIN rw0_rd_out[16]
    DIRECTION OUTPUT ;
    USE SIGNAL ;
    SHAPE ABUTMENT ;
    PORT
      LAYER metal2 ;
      RECT 247.345 0.000 247.415 0.210 ;
    END
  END rw0_rd_out[16]
  PIN rw0_rd_out[17]
    DIRECTION OUTPUT ;
    USE SIGNAL ;
    SHAPE ABUTMENT ;
    PORT
      LAYER metal2 ;
      RECT 250.385 0.000 250.455 0.210 ;
    END
  END rw0_rd_out[17]
  PIN rw0_rd_out[18]
    DIRECTION OUTPUT ;
    USE SIGNAL ;
    SHAPE ABUTMENT ;
    PORT
      LAYER metal2 ;
      RECT 253.425 0.000 253.495 0.210 ;
    END
  END rw0_rd_out[18]
  PIN rw0_rd_out[19]
    DIRECTION OUTPUT ;
    USE SIGNAL ;
    SHAPE ABUTMENT ;
    PORT
      LAYER metal2 ;
      RECT 256.465 0.000 256.535 0.210 ;
    END
  END rw0_rd_out[19]
  PIN rw0_rd_out[20]
    DIRECTION OUTPUT ;
    USE SIGNAL ;
    SHAPE ABUTMENT ;
    PORT
      LAYER metal2 ;
      RECT 259.505 0.000 259.575 0.210 ;
    END
  END rw0_rd_out[20]
  PIN rw0_rd_out[21]
    DIRECTION OUTPUT ;
    USE SIGNAL ;
    SHAPE ABUTMENT ;
    PORT
      LAYER metal2 ;
      RECT 262.545 0.000 262.615 0.210 ;
    END
  END rw0_rd_out[21]
  PIN rw0_rd_out[22]
    DIRECTION OUTPUT ;
    USE SIGNAL ;
    SHAPE ABUTMENT ;
    PORT
      LAYER metal2 ;
      RECT 265.585 0.000 265.655 0.210 ;
    END
  END rw0_rd_out[22]
  PIN rw0_rd_out[23]
    DIRECTION OUTPUT ;
    USE SIGNAL ;
    SHAPE ABUTMENT ;
    PORT
      LAYER metal2 ;
      RECT 268.625 0.000 268.695 0.210 ;
    END
  END rw0_rd_out[23]
  PIN rw0_rd_out[24]
    DIRECTION OUTPUT ;
    USE SIGNAL ;
    SHAPE ABUTMENT ;
    PORT
      LAYER metal2 ;
      RECT 271.665 0.000 271.735 0.210 ;
    END
  END rw0_rd_out[24]
  PIN rw0_rd_out[25]
    DIRECTION OUTPUT ;
    USE SIGNAL ;
    SHAPE ABUTMENT ;
    PORT
      LAYER metal2 ;
      RECT 274.705 0.000 274.775 0.210 ;
    END
  END rw0_rd_out[25]
  PIN rw0_rd_out[26]
    DIRECTION OUTPUT ;
    USE SIGNAL ;
    SHAPE ABUTMENT ;
    PORT
      LAYER metal2 ;
      RECT 277.745 0.000 277.815 0.210 ;
    END
  END rw0_rd_out[26]
  PIN rw0_rd_out[27]
    DIRECTION OUTPUT ;
    USE SIGNAL ;
    SHAPE ABUTMENT ;
    PORT
      LAYER metal2 ;
      RECT 280.785 0.000 280.855 0.210 ;
    END
  END rw0_rd_out[27]
  PIN rw0_rd_out[28]
    DIRECTION OUTPUT ;
    USE SIGNAL ;
    SHAPE ABUTMENT ;
    PORT
      LAYER metal2 ;
      RECT 283.825 0.000 283.895 0.210 ;
    END
  END rw0_rd_out[28]
  PIN rw0_rd_out[29]
    DIRECTION OUTPUT ;
    USE SIGNAL ;
    SHAPE ABUTMENT ;
    PORT
      LAYER metal2 ;
      RECT 286.865 0.000 286.935 0.210 ;
    END
  END rw0_rd_out[29]
  PIN rw0_rd_out[30]
    DIRECTION OUTPUT ;
    USE SIGNAL ;
    SHAPE ABUTMENT ;
    PORT
      LAYER metal2 ;
      RECT 289.905 0.000 289.975 0.210 ;
    END
  END rw0_rd_out[30]
  PIN rw0_rd_out[31]
    DIRECTION OUTPUT ;
    USE SIGNAL ;
    SHAPE ABUTMENT ;
    PORT
      LAYER metal2 ;
      RECT 292.945 0.000 293.015 0.210 ;
    END
  END rw0_rd_out[31]
  PIN rw0_rd_out[32]
    DIRECTION OUTPUT ;
    USE SIGNAL ;
    SHAPE ABUTMENT ;
    PORT
      LAYER metal2 ;
      RECT 295.985 0.000 296.055 0.210 ;
    END
  END rw0_rd_out[32]
  PIN rw0_rd_out[33]
    DIRECTION OUTPUT ;
    USE SIGNAL ;
    SHAPE ABUTMENT ;
    PORT
      LAYER metal2 ;
      RECT 299.025 0.000 299.095 0.210 ;
    END
  END rw0_rd_out[33]
  PIN rw0_rd_out[34]
    DIRECTION OUTPUT ;
    USE SIGNAL ;
    SHAPE ABUTMENT ;
    PORT
      LAYER metal2 ;
      RECT 302.065 0.000 302.135 0.210 ;
    END
  END rw0_rd_out[34]
  PIN rw0_rd_out[35]
    DIRECTION OUTPUT ;
    USE SIGNAL ;
    SHAPE ABUTMENT ;
    PORT
      LAYER metal2 ;
      RECT 305.105 0.000 305.175 0.210 ;
    END
  END rw0_rd_out[35]
  PIN rw0_rd_out[36]
    DIRECTION OUTPUT ;
    USE SIGNAL ;
    SHAPE ABUTMENT ;
    PORT
      LAYER metal2 ;
      RECT 308.145 0.000 308.215 0.210 ;
    END
  END rw0_rd_out[36]
  PIN rw0_rd_out[37]
    DIRECTION OUTPUT ;
    USE SIGNAL ;
    SHAPE ABUTMENT ;
    PORT
      LAYER metal2 ;
      RECT 311.185 0.000 311.255 0.210 ;
    END
  END rw0_rd_out[37]
  PIN rw0_rd_out[38]
    DIRECTION OUTPUT ;
    USE SIGNAL ;
    SHAPE ABUTMENT ;
    PORT
      LAYER metal2 ;
      RECT 314.225 0.000 314.295 0.210 ;
    END
  END rw0_rd_out[38]
  PIN rw0_rd_out[39]
    DIRECTION OUTPUT ;
    USE SIGNAL ;
    SHAPE ABUTMENT ;
    PORT
      LAYER metal2 ;
      RECT 317.265 0.000 317.335 0.210 ;
    END
  END rw0_rd_out[39]
  PIN rw0_rd_out[40]
    DIRECTION OUTPUT ;
    USE SIGNAL ;
    SHAPE ABUTMENT ;
    PORT
      LAYER metal2 ;
      RECT 320.305 0.000 320.375 0.210 ;
    END
  END rw0_rd_out[40]
  PIN rw0_rd_out[41]
    DIRECTION OUTPUT ;
    USE SIGNAL ;
    SHAPE ABUTMENT ;
    PORT
      LAYER metal2 ;
      RECT 323.345 0.000 323.415 0.210 ;
    END
  END rw0_rd_out[41]
  PIN rw0_rd_out[42]
    DIRECTION OUTPUT ;
    USE SIGNAL ;
    SHAPE ABUTMENT ;
    PORT
      LAYER metal2 ;
      RECT 326.385 0.000 326.455 0.210 ;
    END
  END rw0_rd_out[42]
  PIN rw0_rd_out[43]
    DIRECTION OUTPUT ;
    USE SIGNAL ;
    SHAPE ABUTMENT ;
    PORT
      LAYER metal2 ;
      RECT 329.425 0.000 329.495 0.210 ;
    END
  END rw0_rd_out[43]
  PIN rw0_rd_out[44]
    DIRECTION OUTPUT ;
    USE SIGNAL ;
    SHAPE ABUTMENT ;
    PORT
      LAYER metal2 ;
      RECT 332.465 0.000 332.535 0.210 ;
    END
  END rw0_rd_out[44]
  PIN rw0_rd_out[45]
    DIRECTION OUTPUT ;
    USE SIGNAL ;
    SHAPE ABUTMENT ;
    PORT
      LAYER metal2 ;
      RECT 335.505 0.000 335.575 0.210 ;
    END
  END rw0_rd_out[45]
  PIN rw0_rd_out[46]
    DIRECTION OUTPUT ;
    USE SIGNAL ;
    SHAPE ABUTMENT ;
    PORT
      LAYER metal2 ;
      RECT 338.545 0.000 338.615 0.210 ;
    END
  END rw0_rd_out[46]
  PIN rw0_rd_out[47]
    DIRECTION OUTPUT ;
    USE SIGNAL ;
    SHAPE ABUTMENT ;
    PORT
      LAYER metal2 ;
      RECT 341.585 0.000 341.655 0.210 ;
    END
  END rw0_rd_out[47]
  PIN rw0_rd_out[48]
    DIRECTION OUTPUT ;
    USE SIGNAL ;
    SHAPE ABUTMENT ;
    PORT
      LAYER metal2 ;
      RECT 344.625 0.000 344.695 0.210 ;
    END
  END rw0_rd_out[48]
  PIN rw0_rd_out[49]
    DIRECTION OUTPUT ;
    USE SIGNAL ;
    SHAPE ABUTMENT ;
    PORT
      LAYER metal2 ;
      RECT 347.665 0.000 347.735 0.210 ;
    END
  END rw0_rd_out[49]
  PIN rw0_rd_out[50]
    DIRECTION OUTPUT ;
    USE SIGNAL ;
    SHAPE ABUTMENT ;
    PORT
      LAYER metal2 ;
      RECT 350.705 0.000 350.775 0.210 ;
    END
  END rw0_rd_out[50]
  PIN rw0_rd_out[51]
    DIRECTION OUTPUT ;
    USE SIGNAL ;
    SHAPE ABUTMENT ;
    PORT
      LAYER metal2 ;
      RECT 353.745 0.000 353.815 0.210 ;
    END
  END rw0_rd_out[51]
  PIN rw0_rd_out[52]
    DIRECTION OUTPUT ;
    USE SIGNAL ;
    SHAPE ABUTMENT ;
    PORT
      LAYER metal2 ;
      RECT 356.785 0.000 356.855 0.210 ;
    END
  END rw0_rd_out[52]
  PIN rw0_rd_out[53]
    DIRECTION OUTPUT ;
    USE SIGNAL ;
    SHAPE ABUTMENT ;
    PORT
      LAYER metal2 ;
      RECT 359.825 0.000 359.895 0.210 ;
    END
  END rw0_rd_out[53]
  PIN rw0_rd_out[54]
    DIRECTION OUTPUT ;
    USE SIGNAL ;
    SHAPE ABUTMENT ;
    PORT
      LAYER metal2 ;
      RECT 362.865 0.000 362.935 0.210 ;
    END
  END rw0_rd_out[54]
  PIN rw0_rd_out[55]
    DIRECTION OUTPUT ;
    USE SIGNAL ;
    SHAPE ABUTMENT ;
    PORT
      LAYER metal2 ;
      RECT 365.905 0.000 365.975 0.210 ;
    END
  END rw0_rd_out[55]
  PIN rw0_rd_out[56]
    DIRECTION OUTPUT ;
    USE SIGNAL ;
    SHAPE ABUTMENT ;
    PORT
      LAYER metal2 ;
      RECT 368.945 0.000 369.015 0.210 ;
    END
  END rw0_rd_out[56]
  PIN rw0_rd_out[57]
    DIRECTION OUTPUT ;
    USE SIGNAL ;
    SHAPE ABUTMENT ;
    PORT
      LAYER metal2 ;
      RECT 371.985 0.000 372.055 0.210 ;
    END
  END rw0_rd_out[57]
  PIN rw0_rd_out[58]
    DIRECTION OUTPUT ;
    USE SIGNAL ;
    SHAPE ABUTMENT ;
    PORT
      LAYER metal2 ;
      RECT 375.025 0.000 375.095 0.210 ;
    END
  END rw0_rd_out[58]
  PIN rw0_rd_out[59]
    DIRECTION OUTPUT ;
    USE SIGNAL ;
    SHAPE ABUTMENT ;
    PORT
      LAYER metal2 ;
      RECT 378.065 0.000 378.135 0.210 ;
    END
  END rw0_rd_out[59]
  PIN rw0_rd_out[60]
    DIRECTION OUTPUT ;
    USE SIGNAL ;
    SHAPE ABUTMENT ;
    PORT
      LAYER metal2 ;
      RECT 381.105 0.000 381.175 0.210 ;
    END
  END rw0_rd_out[60]
  PIN rw0_rd_out[61]
    DIRECTION OUTPUT ;
    USE SIGNAL ;
    SHAPE ABUTMENT ;
    PORT
      LAYER metal2 ;
      RECT 384.145 0.000 384.215 0.210 ;
    END
  END rw0_rd_out[61]
  PIN rw0_rd_out[62]
    DIRECTION OUTPUT ;
    USE SIGNAL ;
    SHAPE ABUTMENT ;
    PORT
      LAYER metal2 ;
      RECT 387.185 0.000 387.255 0.210 ;
    END
  END rw0_rd_out[62]
  PIN rw0_rd_out[63]
    DIRECTION OUTPUT ;
    USE SIGNAL ;
    SHAPE ABUTMENT ;
    PORT
      LAYER metal2 ;
      RECT 390.225 0.000 390.295 0.210 ;
    END
  END rw0_rd_out[63]
  PIN rw0_rd_out[64]
    DIRECTION OUTPUT ;
    USE SIGNAL ;
    SHAPE ABUTMENT ;
    PORT
      LAYER metal2 ;
      RECT 393.265 0.000 393.335 0.210 ;
    END
  END rw0_rd_out[64]
  PIN rw0_rd_out[65]
    DIRECTION OUTPUT ;
    USE SIGNAL ;
    SHAPE ABUTMENT ;
    PORT
      LAYER metal2 ;
      RECT 1.105 570.990 1.175 571.200 ;
    END
  END rw0_rd_out[65]
  PIN rw0_rd_out[66]
    DIRECTION OUTPUT ;
    USE SIGNAL ;
    SHAPE ABUTMENT ;
    PORT
      LAYER metal2 ;
      RECT 5.475 570.990 5.545 571.200 ;
    END
  END rw0_rd_out[66]
  PIN rw0_rd_out[67]
    DIRECTION OUTPUT ;
    USE SIGNAL ;
    SHAPE ABUTMENT ;
    PORT
      LAYER metal2 ;
      RECT 9.845 570.990 9.915 571.200 ;
    END
  END rw0_rd_out[67]
  PIN rw0_rd_out[68]
    DIRECTION OUTPUT ;
    USE SIGNAL ;
    SHAPE ABUTMENT ;
    PORT
      LAYER metal2 ;
      RECT 14.215 570.990 14.285 571.200 ;
    END
  END rw0_rd_out[68]
  PIN rw0_rd_out[69]
    DIRECTION OUTPUT ;
    USE SIGNAL ;
    SHAPE ABUTMENT ;
    PORT
      LAYER metal2 ;
      RECT 18.585 570.990 18.655 571.200 ;
    END
  END rw0_rd_out[69]
  PIN rw0_rd_out[70]
    DIRECTION OUTPUT ;
    USE SIGNAL ;
    SHAPE ABUTMENT ;
    PORT
      LAYER metal2 ;
      RECT 22.955 570.990 23.025 571.200 ;
    END
  END rw0_rd_out[70]
  PIN rw0_rd_out[71]
    DIRECTION OUTPUT ;
    USE SIGNAL ;
    SHAPE ABUTMENT ;
    PORT
      LAYER metal2 ;
      RECT 27.325 570.990 27.395 571.200 ;
    END
  END rw0_rd_out[71]
  PIN rw0_rd_out[72]
    DIRECTION OUTPUT ;
    USE SIGNAL ;
    SHAPE ABUTMENT ;
    PORT
      LAYER metal2 ;
      RECT 31.695 570.990 31.765 571.200 ;
    END
  END rw0_rd_out[72]
  PIN rw0_rd_out[73]
    DIRECTION OUTPUT ;
    USE SIGNAL ;
    SHAPE ABUTMENT ;
    PORT
      LAYER metal2 ;
      RECT 36.065 570.990 36.135 571.200 ;
    END
  END rw0_rd_out[73]
  PIN rw0_rd_out[74]
    DIRECTION OUTPUT ;
    USE SIGNAL ;
    SHAPE ABUTMENT ;
    PORT
      LAYER metal2 ;
      RECT 40.435 570.990 40.505 571.200 ;
    END
  END rw0_rd_out[74]
  PIN rw0_rd_out[75]
    DIRECTION OUTPUT ;
    USE SIGNAL ;
    SHAPE ABUTMENT ;
    PORT
      LAYER metal2 ;
      RECT 44.805 570.990 44.875 571.200 ;
    END
  END rw0_rd_out[75]
  PIN rw0_rd_out[76]
    DIRECTION OUTPUT ;
    USE SIGNAL ;
    SHAPE ABUTMENT ;
    PORT
      LAYER metal2 ;
      RECT 49.175 570.990 49.245 571.200 ;
    END
  END rw0_rd_out[76]
  PIN rw0_rd_out[77]
    DIRECTION OUTPUT ;
    USE SIGNAL ;
    SHAPE ABUTMENT ;
    PORT
      LAYER metal2 ;
      RECT 53.545 570.990 53.615 571.200 ;
    END
  END rw0_rd_out[77]
  PIN rw0_rd_out[78]
    DIRECTION OUTPUT ;
    USE SIGNAL ;
    SHAPE ABUTMENT ;
    PORT
      LAYER metal2 ;
      RECT 57.915 570.990 57.985 571.200 ;
    END
  END rw0_rd_out[78]
  PIN rw0_rd_out[79]
    DIRECTION OUTPUT ;
    USE SIGNAL ;
    SHAPE ABUTMENT ;
    PORT
      LAYER metal2 ;
      RECT 62.285 570.990 62.355 571.200 ;
    END
  END rw0_rd_out[79]
  PIN rw0_rd_out[80]
    DIRECTION OUTPUT ;
    USE SIGNAL ;
    SHAPE ABUTMENT ;
    PORT
      LAYER metal2 ;
      RECT 66.655 570.990 66.725 571.200 ;
    END
  END rw0_rd_out[80]
  PIN rw0_rd_out[81]
    DIRECTION OUTPUT ;
    USE SIGNAL ;
    SHAPE ABUTMENT ;
    PORT
      LAYER metal2 ;
      RECT 71.025 570.990 71.095 571.200 ;
    END
  END rw0_rd_out[81]
  PIN rw0_rd_out[82]
    DIRECTION OUTPUT ;
    USE SIGNAL ;
    SHAPE ABUTMENT ;
    PORT
      LAYER metal2 ;
      RECT 75.395 570.990 75.465 571.200 ;
    END
  END rw0_rd_out[82]
  PIN rw0_rd_out[83]
    DIRECTION OUTPUT ;
    USE SIGNAL ;
    SHAPE ABUTMENT ;
    PORT
      LAYER metal2 ;
      RECT 79.765 570.990 79.835 571.200 ;
    END
  END rw0_rd_out[83]
  PIN rw0_rd_out[84]
    DIRECTION OUTPUT ;
    USE SIGNAL ;
    SHAPE ABUTMENT ;
    PORT
      LAYER metal2 ;
      RECT 84.135 570.990 84.205 571.200 ;
    END
  END rw0_rd_out[84]
  PIN rw0_rd_out[85]
    DIRECTION OUTPUT ;
    USE SIGNAL ;
    SHAPE ABUTMENT ;
    PORT
      LAYER metal2 ;
      RECT 88.505 570.990 88.575 571.200 ;
    END
  END rw0_rd_out[85]
  PIN rw0_rd_out[86]
    DIRECTION OUTPUT ;
    USE SIGNAL ;
    SHAPE ABUTMENT ;
    PORT
      LAYER metal2 ;
      RECT 92.875 570.990 92.945 571.200 ;
    END
  END rw0_rd_out[86]
  PIN rw0_rd_out[87]
    DIRECTION OUTPUT ;
    USE SIGNAL ;
    SHAPE ABUTMENT ;
    PORT
      LAYER metal2 ;
      RECT 97.245 570.990 97.315 571.200 ;
    END
  END rw0_rd_out[87]
  PIN rw0_rd_out[88]
    DIRECTION OUTPUT ;
    USE SIGNAL ;
    SHAPE ABUTMENT ;
    PORT
      LAYER metal2 ;
      RECT 101.615 570.990 101.685 571.200 ;
    END
  END rw0_rd_out[88]
  PIN rw0_rd_out[89]
    DIRECTION OUTPUT ;
    USE SIGNAL ;
    SHAPE ABUTMENT ;
    PORT
      LAYER metal2 ;
      RECT 105.985 570.990 106.055 571.200 ;
    END
  END rw0_rd_out[89]
  PIN rw0_rd_out[90]
    DIRECTION OUTPUT ;
    USE SIGNAL ;
    SHAPE ABUTMENT ;
    PORT
      LAYER metal2 ;
      RECT 110.355 570.990 110.425 571.200 ;
    END
  END rw0_rd_out[90]
  PIN rw0_rd_out[91]
    DIRECTION OUTPUT ;
    USE SIGNAL ;
    SHAPE ABUTMENT ;
    PORT
      LAYER metal2 ;
      RECT 114.725 570.990 114.795 571.200 ;
    END
  END rw0_rd_out[91]
  PIN rw0_rd_out[92]
    DIRECTION OUTPUT ;
    USE SIGNAL ;
    SHAPE ABUTMENT ;
    PORT
      LAYER metal2 ;
      RECT 119.095 570.990 119.165 571.200 ;
    END
  END rw0_rd_out[92]
  PIN rw0_rd_out[93]
    DIRECTION OUTPUT ;
    USE SIGNAL ;
    SHAPE ABUTMENT ;
    PORT
      LAYER metal2 ;
      RECT 123.465 570.990 123.535 571.200 ;
    END
  END rw0_rd_out[93]
  PIN rw0_rd_out[94]
    DIRECTION OUTPUT ;
    USE SIGNAL ;
    SHAPE ABUTMENT ;
    PORT
      LAYER metal2 ;
      RECT 127.835 570.990 127.905 571.200 ;
    END
  END rw0_rd_out[94]
  PIN rw0_rd_out[95]
    DIRECTION OUTPUT ;
    USE SIGNAL ;
    SHAPE ABUTMENT ;
    PORT
      LAYER metal2 ;
      RECT 132.205 570.990 132.275 571.200 ;
    END
  END rw0_rd_out[95]
  PIN rw0_rd_out[96]
    DIRECTION OUTPUT ;
    USE SIGNAL ;
    SHAPE ABUTMENT ;
    PORT
      LAYER metal2 ;
      RECT 136.575 570.990 136.645 571.200 ;
    END
  END rw0_rd_out[96]
  PIN rw0_rd_out[97]
    DIRECTION OUTPUT ;
    USE SIGNAL ;
    SHAPE ABUTMENT ;
    PORT
      LAYER metal2 ;
      RECT 140.945 570.990 141.015 571.200 ;
    END
  END rw0_rd_out[97]
  PIN rw0_rd_out[98]
    DIRECTION OUTPUT ;
    USE SIGNAL ;
    SHAPE ABUTMENT ;
    PORT
      LAYER metal2 ;
      RECT 145.315 570.990 145.385 571.200 ;
    END
  END rw0_rd_out[98]
  PIN rw0_rd_out[99]
    DIRECTION OUTPUT ;
    USE SIGNAL ;
    SHAPE ABUTMENT ;
    PORT
      LAYER metal2 ;
      RECT 149.685 570.990 149.755 571.200 ;
    END
  END rw0_rd_out[99]
  PIN rw0_rd_out[100]
    DIRECTION OUTPUT ;
    USE SIGNAL ;
    SHAPE ABUTMENT ;
    PORT
      LAYER metal2 ;
      RECT 154.055 570.990 154.125 571.200 ;
    END
  END rw0_rd_out[100]
  PIN rw0_rd_out[101]
    DIRECTION OUTPUT ;
    USE SIGNAL ;
    SHAPE ABUTMENT ;
    PORT
      LAYER metal2 ;
      RECT 158.425 570.990 158.495 571.200 ;
    END
  END rw0_rd_out[101]
  PIN rw0_rd_out[102]
    DIRECTION OUTPUT ;
    USE SIGNAL ;
    SHAPE ABUTMENT ;
    PORT
      LAYER metal2 ;
      RECT 162.795 570.990 162.865 571.200 ;
    END
  END rw0_rd_out[102]
  PIN rw0_rd_out[103]
    DIRECTION OUTPUT ;
    USE SIGNAL ;
    SHAPE ABUTMENT ;
    PORT
      LAYER metal2 ;
      RECT 167.165 570.990 167.235 571.200 ;
    END
  END rw0_rd_out[103]
  PIN rw0_rd_out[104]
    DIRECTION OUTPUT ;
    USE SIGNAL ;
    SHAPE ABUTMENT ;
    PORT
      LAYER metal2 ;
      RECT 171.535 570.990 171.605 571.200 ;
    END
  END rw0_rd_out[104]
  PIN rw0_rd_out[105]
    DIRECTION OUTPUT ;
    USE SIGNAL ;
    SHAPE ABUTMENT ;
    PORT
      LAYER metal2 ;
      RECT 175.905 570.990 175.975 571.200 ;
    END
  END rw0_rd_out[105]
  PIN rw0_rd_out[106]
    DIRECTION OUTPUT ;
    USE SIGNAL ;
    SHAPE ABUTMENT ;
    PORT
      LAYER metal2 ;
      RECT 180.275 570.990 180.345 571.200 ;
    END
  END rw0_rd_out[106]
  PIN rw0_rd_out[107]
    DIRECTION OUTPUT ;
    USE SIGNAL ;
    SHAPE ABUTMENT ;
    PORT
      LAYER metal2 ;
      RECT 184.645 570.990 184.715 571.200 ;
    END
  END rw0_rd_out[107]
  PIN rw0_rd_out[108]
    DIRECTION OUTPUT ;
    USE SIGNAL ;
    SHAPE ABUTMENT ;
    PORT
      LAYER metal2 ;
      RECT 189.015 570.990 189.085 571.200 ;
    END
  END rw0_rd_out[108]
  PIN rw0_rd_out[109]
    DIRECTION OUTPUT ;
    USE SIGNAL ;
    SHAPE ABUTMENT ;
    PORT
      LAYER metal2 ;
      RECT 193.385 570.990 193.455 571.200 ;
    END
  END rw0_rd_out[109]
  PIN rw0_rd_out[110]
    DIRECTION OUTPUT ;
    USE SIGNAL ;
    SHAPE ABUTMENT ;
    PORT
      LAYER metal2 ;
      RECT 197.755 570.990 197.825 571.200 ;
    END
  END rw0_rd_out[110]
  PIN rw0_rd_out[111]
    DIRECTION OUTPUT ;
    USE SIGNAL ;
    SHAPE ABUTMENT ;
    PORT
      LAYER metal2 ;
      RECT 202.125 570.990 202.195 571.200 ;
    END
  END rw0_rd_out[111]
  PIN rw0_rd_out[112]
    DIRECTION OUTPUT ;
    USE SIGNAL ;
    SHAPE ABUTMENT ;
    PORT
      LAYER metal2 ;
      RECT 206.495 570.990 206.565 571.200 ;
    END
  END rw0_rd_out[112]
  PIN rw0_rd_out[113]
    DIRECTION OUTPUT ;
    USE SIGNAL ;
    SHAPE ABUTMENT ;
    PORT
      LAYER metal2 ;
      RECT 210.865 570.990 210.935 571.200 ;
    END
  END rw0_rd_out[113]
  PIN rw0_rd_out[114]
    DIRECTION OUTPUT ;
    USE SIGNAL ;
    SHAPE ABUTMENT ;
    PORT
      LAYER metal2 ;
      RECT 215.235 570.990 215.305 571.200 ;
    END
  END rw0_rd_out[114]
  PIN rw0_rd_out[115]
    DIRECTION OUTPUT ;
    USE SIGNAL ;
    SHAPE ABUTMENT ;
    PORT
      LAYER metal2 ;
      RECT 219.605 570.990 219.675 571.200 ;
    END
  END rw0_rd_out[115]
  PIN rw0_rd_out[116]
    DIRECTION OUTPUT ;
    USE SIGNAL ;
    SHAPE ABUTMENT ;
    PORT
      LAYER metal2 ;
      RECT 223.975 570.990 224.045 571.200 ;
    END
  END rw0_rd_out[116]
  PIN rw0_rd_out[117]
    DIRECTION OUTPUT ;
    USE SIGNAL ;
    SHAPE ABUTMENT ;
    PORT
      LAYER metal2 ;
      RECT 228.345 570.990 228.415 571.200 ;
    END
  END rw0_rd_out[117]
  PIN rw0_rd_out[118]
    DIRECTION OUTPUT ;
    USE SIGNAL ;
    SHAPE ABUTMENT ;
    PORT
      LAYER metal2 ;
      RECT 232.715 570.990 232.785 571.200 ;
    END
  END rw0_rd_out[118]
  PIN rw0_rd_out[119]
    DIRECTION OUTPUT ;
    USE SIGNAL ;
    SHAPE ABUTMENT ;
    PORT
      LAYER metal2 ;
      RECT 237.085 570.990 237.155 571.200 ;
    END
  END rw0_rd_out[119]
  PIN rw0_rd_out[120]
    DIRECTION OUTPUT ;
    USE SIGNAL ;
    SHAPE ABUTMENT ;
    PORT
      LAYER metal2 ;
      RECT 241.455 570.990 241.525 571.200 ;
    END
  END rw0_rd_out[120]
  PIN rw0_rd_out[121]
    DIRECTION OUTPUT ;
    USE SIGNAL ;
    SHAPE ABUTMENT ;
    PORT
      LAYER metal2 ;
      RECT 245.825 570.990 245.895 571.200 ;
    END
  END rw0_rd_out[121]
  PIN rw0_rd_out[122]
    DIRECTION OUTPUT ;
    USE SIGNAL ;
    SHAPE ABUTMENT ;
    PORT
      LAYER metal2 ;
      RECT 250.195 570.990 250.265 571.200 ;
    END
  END rw0_rd_out[122]
  PIN rw0_rd_out[123]
    DIRECTION OUTPUT ;
    USE SIGNAL ;
    SHAPE ABUTMENT ;
    PORT
      LAYER metal2 ;
      RECT 254.565 570.990 254.635 571.200 ;
    END
  END rw0_rd_out[123]
  PIN rw0_rd_out[124]
    DIRECTION OUTPUT ;
    USE SIGNAL ;
    SHAPE ABUTMENT ;
    PORT
      LAYER metal2 ;
      RECT 258.935 570.990 259.005 571.200 ;
    END
  END rw0_rd_out[124]
  PIN rw0_rd_out[125]
    DIRECTION OUTPUT ;
    USE SIGNAL ;
    SHAPE ABUTMENT ;
    PORT
      LAYER metal2 ;
      RECT 263.305 570.990 263.375 571.200 ;
    END
  END rw0_rd_out[125]
  PIN rw0_rd_out[126]
    DIRECTION OUTPUT ;
    USE SIGNAL ;
    SHAPE ABUTMENT ;
    PORT
      LAYER metal2 ;
      RECT 267.675 570.990 267.745 571.200 ;
    END
  END rw0_rd_out[126]
  PIN rw0_rd_out[127]
    DIRECTION OUTPUT ;
    USE SIGNAL ;
    SHAPE ABUTMENT ;
    PORT
      LAYER metal2 ;
      RECT 272.045 570.990 272.115 571.200 ;
    END
  END rw0_rd_out[127]
  PIN rw0_rd_out[128]
    DIRECTION OUTPUT ;
    USE SIGNAL ;
    SHAPE ABUTMENT ;
    PORT
      LAYER metal2 ;
      RECT 276.415 570.990 276.485 571.200 ;
    END
  END rw0_rd_out[128]
  PIN rw0_rd_out[129]
    DIRECTION OUTPUT ;
    USE SIGNAL ;
    SHAPE ABUTMENT ;
    PORT
      LAYER metal2 ;
      RECT 280.785 570.990 280.855 571.200 ;
    END
  END rw0_rd_out[129]
  PIN r0_rd_out[0]
    DIRECTION OUTPUT ;
    USE SIGNAL ;
    SHAPE ABUTMENT ;
    PORT
      LAYER metal2 ;
      RECT 396.305 0.000 396.375 0.210 ;
    END
  END r0_rd_out[0]
  PIN r0_rd_out[1]
    DIRECTION OUTPUT ;
    USE SIGNAL ;
    SHAPE ABUTMENT ;
    PORT
      LAYER metal2 ;
      RECT 399.345 0.000 399.415 0.210 ;
    END
  END r0_rd_out[1]
  PIN r0_rd_out[2]
    DIRECTION OUTPUT ;
    USE SIGNAL ;
    SHAPE ABUTMENT ;
    PORT
      LAYER metal2 ;
      RECT 402.385 0.000 402.455 0.210 ;
    END
  END r0_rd_out[2]
  PIN r0_rd_out[3]
    DIRECTION OUTPUT ;
    USE SIGNAL ;
    SHAPE ABUTMENT ;
    PORT
      LAYER metal2 ;
      RECT 405.425 0.000 405.495 0.210 ;
    END
  END r0_rd_out[3]
  PIN r0_rd_out[4]
    DIRECTION OUTPUT ;
    USE SIGNAL ;
    SHAPE ABUTMENT ;
    PORT
      LAYER metal2 ;
      RECT 408.465 0.000 408.535 0.210 ;
    END
  END r0_rd_out[4]
  PIN r0_rd_out[5]
    DIRECTION OUTPUT ;
    USE SIGNAL ;
    SHAPE ABUTMENT ;
    PORT
      LAYER metal2 ;
      RECT 411.505 0.000 411.575 0.210 ;
    END
  END r0_rd_out[5]
  PIN r0_rd_out[6]
    DIRECTION OUTPUT ;
    USE SIGNAL ;
    SHAPE ABUTMENT ;
    PORT
      LAYER metal2 ;
      RECT 414.545 0.000 414.615 0.210 ;
    END
  END r0_rd_out[6]
  PIN r0_rd_out[7]
    DIRECTION OUTPUT ;
    USE SIGNAL ;
    SHAPE ABUTMENT ;
    PORT
      LAYER metal2 ;
      RECT 417.585 0.000 417.655 0.210 ;
    END
  END r0_rd_out[7]
  PIN r0_rd_out[8]
    DIRECTION OUTPUT ;
    USE SIGNAL ;
    SHAPE ABUTMENT ;
    PORT
      LAYER metal2 ;
      RECT 420.625 0.000 420.695 0.210 ;
    END
  END r0_rd_out[8]
  PIN r0_rd_out[9]
    DIRECTION OUTPUT ;
    USE SIGNAL ;
    SHAPE ABUTMENT ;
    PORT
      LAYER metal2 ;
      RECT 423.665 0.000 423.735 0.210 ;
    END
  END r0_rd_out[9]
  PIN r0_rd_out[10]
    DIRECTION OUTPUT ;
    USE SIGNAL ;
    SHAPE ABUTMENT ;
    PORT
      LAYER metal2 ;
      RECT 426.705 0.000 426.775 0.210 ;
    END
  END r0_rd_out[10]
  PIN r0_rd_out[11]
    DIRECTION OUTPUT ;
    USE SIGNAL ;
    SHAPE ABUTMENT ;
    PORT
      LAYER metal2 ;
      RECT 429.745 0.000 429.815 0.210 ;
    END
  END r0_rd_out[11]
  PIN r0_rd_out[12]
    DIRECTION OUTPUT ;
    USE SIGNAL ;
    SHAPE ABUTMENT ;
    PORT
      LAYER metal2 ;
      RECT 432.785 0.000 432.855 0.210 ;
    END
  END r0_rd_out[12]
  PIN r0_rd_out[13]
    DIRECTION OUTPUT ;
    USE SIGNAL ;
    SHAPE ABUTMENT ;
    PORT
      LAYER metal2 ;
      RECT 435.825 0.000 435.895 0.210 ;
    END
  END r0_rd_out[13]
  PIN r0_rd_out[14]
    DIRECTION OUTPUT ;
    USE SIGNAL ;
    SHAPE ABUTMENT ;
    PORT
      LAYER metal2 ;
      RECT 438.865 0.000 438.935 0.210 ;
    END
  END r0_rd_out[14]
  PIN r0_rd_out[15]
    DIRECTION OUTPUT ;
    USE SIGNAL ;
    SHAPE ABUTMENT ;
    PORT
      LAYER metal2 ;
      RECT 441.905 0.000 441.975 0.210 ;
    END
  END r0_rd_out[15]
  PIN r0_rd_out[16]
    DIRECTION OUTPUT ;
    USE SIGNAL ;
    SHAPE ABUTMENT ;
    PORT
      LAYER metal2 ;
      RECT 444.945 0.000 445.015 0.210 ;
    END
  END r0_rd_out[16]
  PIN r0_rd_out[17]
    DIRECTION OUTPUT ;
    USE SIGNAL ;
    SHAPE ABUTMENT ;
    PORT
      LAYER metal2 ;
      RECT 447.985 0.000 448.055 0.210 ;
    END
  END r0_rd_out[17]
  PIN r0_rd_out[18]
    DIRECTION OUTPUT ;
    USE SIGNAL ;
    SHAPE ABUTMENT ;
    PORT
      LAYER metal2 ;
      RECT 451.025 0.000 451.095 0.210 ;
    END
  END r0_rd_out[18]
  PIN r0_rd_out[19]
    DIRECTION OUTPUT ;
    USE SIGNAL ;
    SHAPE ABUTMENT ;
    PORT
      LAYER metal2 ;
      RECT 454.065 0.000 454.135 0.210 ;
    END
  END r0_rd_out[19]
  PIN r0_rd_out[20]
    DIRECTION OUTPUT ;
    USE SIGNAL ;
    SHAPE ABUTMENT ;
    PORT
      LAYER metal2 ;
      RECT 457.105 0.000 457.175 0.210 ;
    END
  END r0_rd_out[20]
  PIN r0_rd_out[21]
    DIRECTION OUTPUT ;
    USE SIGNAL ;
    SHAPE ABUTMENT ;
    PORT
      LAYER metal2 ;
      RECT 460.145 0.000 460.215 0.210 ;
    END
  END r0_rd_out[21]
  PIN r0_rd_out[22]
    DIRECTION OUTPUT ;
    USE SIGNAL ;
    SHAPE ABUTMENT ;
    PORT
      LAYER metal2 ;
      RECT 463.185 0.000 463.255 0.210 ;
    END
  END r0_rd_out[22]
  PIN r0_rd_out[23]
    DIRECTION OUTPUT ;
    USE SIGNAL ;
    SHAPE ABUTMENT ;
    PORT
      LAYER metal2 ;
      RECT 466.225 0.000 466.295 0.210 ;
    END
  END r0_rd_out[23]
  PIN r0_rd_out[24]
    DIRECTION OUTPUT ;
    USE SIGNAL ;
    SHAPE ABUTMENT ;
    PORT
      LAYER metal2 ;
      RECT 469.265 0.000 469.335 0.210 ;
    END
  END r0_rd_out[24]
  PIN r0_rd_out[25]
    DIRECTION OUTPUT ;
    USE SIGNAL ;
    SHAPE ABUTMENT ;
    PORT
      LAYER metal2 ;
      RECT 472.305 0.000 472.375 0.210 ;
    END
  END r0_rd_out[25]
  PIN r0_rd_out[26]
    DIRECTION OUTPUT ;
    USE SIGNAL ;
    SHAPE ABUTMENT ;
    PORT
      LAYER metal2 ;
      RECT 475.345 0.000 475.415 0.210 ;
    END
  END r0_rd_out[26]
  PIN r0_rd_out[27]
    DIRECTION OUTPUT ;
    USE SIGNAL ;
    SHAPE ABUTMENT ;
    PORT
      LAYER metal2 ;
      RECT 478.385 0.000 478.455 0.210 ;
    END
  END r0_rd_out[27]
  PIN r0_rd_out[28]
    DIRECTION OUTPUT ;
    USE SIGNAL ;
    SHAPE ABUTMENT ;
    PORT
      LAYER metal2 ;
      RECT 481.425 0.000 481.495 0.210 ;
    END
  END r0_rd_out[28]
  PIN r0_rd_out[29]
    DIRECTION OUTPUT ;
    USE SIGNAL ;
    SHAPE ABUTMENT ;
    PORT
      LAYER metal2 ;
      RECT 484.465 0.000 484.535 0.210 ;
    END
  END r0_rd_out[29]
  PIN r0_rd_out[30]
    DIRECTION OUTPUT ;
    USE SIGNAL ;
    SHAPE ABUTMENT ;
    PORT
      LAYER metal2 ;
      RECT 487.505 0.000 487.575 0.210 ;
    END
  END r0_rd_out[30]
  PIN r0_rd_out[31]
    DIRECTION OUTPUT ;
    USE SIGNAL ;
    SHAPE ABUTMENT ;
    PORT
      LAYER metal2 ;
      RECT 490.545 0.000 490.615 0.210 ;
    END
  END r0_rd_out[31]
  PIN r0_rd_out[32]
    DIRECTION OUTPUT ;
    USE SIGNAL ;
    SHAPE ABUTMENT ;
    PORT
      LAYER metal2 ;
      RECT 493.585 0.000 493.655 0.210 ;
    END
  END r0_rd_out[32]
  PIN r0_rd_out[33]
    DIRECTION OUTPUT ;
    USE SIGNAL ;
    SHAPE ABUTMENT ;
    PORT
      LAYER metal2 ;
      RECT 496.625 0.000 496.695 0.210 ;
    END
  END r0_rd_out[33]
  PIN r0_rd_out[34]
    DIRECTION OUTPUT ;
    USE SIGNAL ;
    SHAPE ABUTMENT ;
    PORT
      LAYER metal2 ;
      RECT 499.665 0.000 499.735 0.210 ;
    END
  END r0_rd_out[34]
  PIN r0_rd_out[35]
    DIRECTION OUTPUT ;
    USE SIGNAL ;
    SHAPE ABUTMENT ;
    PORT
      LAYER metal2 ;
      RECT 502.705 0.000 502.775 0.210 ;
    END
  END r0_rd_out[35]
  PIN r0_rd_out[36]
    DIRECTION OUTPUT ;
    USE SIGNAL ;
    SHAPE ABUTMENT ;
    PORT
      LAYER metal2 ;
      RECT 505.745 0.000 505.815 0.210 ;
    END
  END r0_rd_out[36]
  PIN r0_rd_out[37]
    DIRECTION OUTPUT ;
    USE SIGNAL ;
    SHAPE ABUTMENT ;
    PORT
      LAYER metal2 ;
      RECT 508.785 0.000 508.855 0.210 ;
    END
  END r0_rd_out[37]
  PIN r0_rd_out[38]
    DIRECTION OUTPUT ;
    USE SIGNAL ;
    SHAPE ABUTMENT ;
    PORT
      LAYER metal2 ;
      RECT 511.825 0.000 511.895 0.210 ;
    END
  END r0_rd_out[38]
  PIN r0_rd_out[39]
    DIRECTION OUTPUT ;
    USE SIGNAL ;
    SHAPE ABUTMENT ;
    PORT
      LAYER metal2 ;
      RECT 514.865 0.000 514.935 0.210 ;
    END
  END r0_rd_out[39]
  PIN r0_rd_out[40]
    DIRECTION OUTPUT ;
    USE SIGNAL ;
    SHAPE ABUTMENT ;
    PORT
      LAYER metal2 ;
      RECT 517.905 0.000 517.975 0.210 ;
    END
  END r0_rd_out[40]
  PIN r0_rd_out[41]
    DIRECTION OUTPUT ;
    USE SIGNAL ;
    SHAPE ABUTMENT ;
    PORT
      LAYER metal2 ;
      RECT 520.945 0.000 521.015 0.210 ;
    END
  END r0_rd_out[41]
  PIN r0_rd_out[42]
    DIRECTION OUTPUT ;
    USE SIGNAL ;
    SHAPE ABUTMENT ;
    PORT
      LAYER metal2 ;
      RECT 523.985 0.000 524.055 0.210 ;
    END
  END r0_rd_out[42]
  PIN r0_rd_out[43]
    DIRECTION OUTPUT ;
    USE SIGNAL ;
    SHAPE ABUTMENT ;
    PORT
      LAYER metal2 ;
      RECT 527.025 0.000 527.095 0.210 ;
    END
  END r0_rd_out[43]
  PIN r0_rd_out[44]
    DIRECTION OUTPUT ;
    USE SIGNAL ;
    SHAPE ABUTMENT ;
    PORT
      LAYER metal2 ;
      RECT 530.065 0.000 530.135 0.210 ;
    END
  END r0_rd_out[44]
  PIN r0_rd_out[45]
    DIRECTION OUTPUT ;
    USE SIGNAL ;
    SHAPE ABUTMENT ;
    PORT
      LAYER metal2 ;
      RECT 533.105 0.000 533.175 0.210 ;
    END
  END r0_rd_out[45]
  PIN r0_rd_out[46]
    DIRECTION OUTPUT ;
    USE SIGNAL ;
    SHAPE ABUTMENT ;
    PORT
      LAYER metal2 ;
      RECT 536.145 0.000 536.215 0.210 ;
    END
  END r0_rd_out[46]
  PIN r0_rd_out[47]
    DIRECTION OUTPUT ;
    USE SIGNAL ;
    SHAPE ABUTMENT ;
    PORT
      LAYER metal2 ;
      RECT 539.185 0.000 539.255 0.210 ;
    END
  END r0_rd_out[47]
  PIN r0_rd_out[48]
    DIRECTION OUTPUT ;
    USE SIGNAL ;
    SHAPE ABUTMENT ;
    PORT
      LAYER metal2 ;
      RECT 542.225 0.000 542.295 0.210 ;
    END
  END r0_rd_out[48]
  PIN r0_rd_out[49]
    DIRECTION OUTPUT ;
    USE SIGNAL ;
    SHAPE ABUTMENT ;
    PORT
      LAYER metal2 ;
      RECT 545.265 0.000 545.335 0.210 ;
    END
  END r0_rd_out[49]
  PIN r0_rd_out[50]
    DIRECTION OUTPUT ;
    USE SIGNAL ;
    SHAPE ABUTMENT ;
    PORT
      LAYER metal2 ;
      RECT 548.305 0.000 548.375 0.210 ;
    END
  END r0_rd_out[50]
  PIN r0_rd_out[51]
    DIRECTION OUTPUT ;
    USE SIGNAL ;
    SHAPE ABUTMENT ;
    PORT
      LAYER metal2 ;
      RECT 551.345 0.000 551.415 0.210 ;
    END
  END r0_rd_out[51]
  PIN r0_rd_out[52]
    DIRECTION OUTPUT ;
    USE SIGNAL ;
    SHAPE ABUTMENT ;
    PORT
      LAYER metal2 ;
      RECT 554.385 0.000 554.455 0.210 ;
    END
  END r0_rd_out[52]
  PIN r0_rd_out[53]
    DIRECTION OUTPUT ;
    USE SIGNAL ;
    SHAPE ABUTMENT ;
    PORT
      LAYER metal2 ;
      RECT 557.425 0.000 557.495 0.210 ;
    END
  END r0_rd_out[53]
  PIN r0_rd_out[54]
    DIRECTION OUTPUT ;
    USE SIGNAL ;
    SHAPE ABUTMENT ;
    PORT
      LAYER metal2 ;
      RECT 560.465 0.000 560.535 0.210 ;
    END
  END r0_rd_out[54]
  PIN r0_rd_out[55]
    DIRECTION OUTPUT ;
    USE SIGNAL ;
    SHAPE ABUTMENT ;
    PORT
      LAYER metal2 ;
      RECT 563.505 0.000 563.575 0.210 ;
    END
  END r0_rd_out[55]
  PIN r0_rd_out[56]
    DIRECTION OUTPUT ;
    USE SIGNAL ;
    SHAPE ABUTMENT ;
    PORT
      LAYER metal2 ;
      RECT 566.545 0.000 566.615 0.210 ;
    END
  END r0_rd_out[56]
  PIN r0_rd_out[57]
    DIRECTION OUTPUT ;
    USE SIGNAL ;
    SHAPE ABUTMENT ;
    PORT
      LAYER metal2 ;
      RECT 569.585 0.000 569.655 0.210 ;
    END
  END r0_rd_out[57]
  PIN r0_rd_out[58]
    DIRECTION OUTPUT ;
    USE SIGNAL ;
    SHAPE ABUTMENT ;
    PORT
      LAYER metal2 ;
      RECT 572.625 0.000 572.695 0.210 ;
    END
  END r0_rd_out[58]
  PIN r0_rd_out[59]
    DIRECTION OUTPUT ;
    USE SIGNAL ;
    SHAPE ABUTMENT ;
    PORT
      LAYER metal2 ;
      RECT 575.665 0.000 575.735 0.210 ;
    END
  END r0_rd_out[59]
  PIN r0_rd_out[60]
    DIRECTION OUTPUT ;
    USE SIGNAL ;
    SHAPE ABUTMENT ;
    PORT
      LAYER metal2 ;
      RECT 578.705 0.000 578.775 0.210 ;
    END
  END r0_rd_out[60]
  PIN r0_rd_out[61]
    DIRECTION OUTPUT ;
    USE SIGNAL ;
    SHAPE ABUTMENT ;
    PORT
      LAYER metal2 ;
      RECT 581.745 0.000 581.815 0.210 ;
    END
  END r0_rd_out[61]
  PIN r0_rd_out[62]
    DIRECTION OUTPUT ;
    USE SIGNAL ;
    SHAPE ABUTMENT ;
    PORT
      LAYER metal2 ;
      RECT 584.785 0.000 584.855 0.210 ;
    END
  END r0_rd_out[62]
  PIN r0_rd_out[63]
    DIRECTION OUTPUT ;
    USE SIGNAL ;
    SHAPE ABUTMENT ;
    PORT
      LAYER metal2 ;
      RECT 587.825 0.000 587.895 0.210 ;
    END
  END r0_rd_out[63]
  PIN r0_rd_out[64]
    DIRECTION OUTPUT ;
    USE SIGNAL ;
    SHAPE ABUTMENT ;
    PORT
      LAYER metal2 ;
      RECT 590.865 0.000 590.935 0.210 ;
    END
  END r0_rd_out[64]
  PIN r0_rd_out[65]
    DIRECTION OUTPUT ;
    USE SIGNAL ;
    SHAPE ABUTMENT ;
    PORT
      LAYER metal2 ;
      RECT 285.155 570.990 285.225 571.200 ;
    END
  END r0_rd_out[65]
  PIN r0_rd_out[66]
    DIRECTION OUTPUT ;
    USE SIGNAL ;
    SHAPE ABUTMENT ;
    PORT
      LAYER metal2 ;
      RECT 289.525 570.990 289.595 571.200 ;
    END
  END r0_rd_out[66]
  PIN r0_rd_out[67]
    DIRECTION OUTPUT ;
    USE SIGNAL ;
    SHAPE ABUTMENT ;
    PORT
      LAYER metal2 ;
      RECT 293.895 570.990 293.965 571.200 ;
    END
  END r0_rd_out[67]
  PIN r0_rd_out[68]
    DIRECTION OUTPUT ;
    USE SIGNAL ;
    SHAPE ABUTMENT ;
    PORT
      LAYER metal2 ;
      RECT 298.265 570.990 298.335 571.200 ;
    END
  END r0_rd_out[68]
  PIN r0_rd_out[69]
    DIRECTION OUTPUT ;
    USE SIGNAL ;
    SHAPE ABUTMENT ;
    PORT
      LAYER metal2 ;
      RECT 302.635 570.990 302.705 571.200 ;
    END
  END r0_rd_out[69]
  PIN r0_rd_out[70]
    DIRECTION OUTPUT ;
    USE SIGNAL ;
    SHAPE ABUTMENT ;
    PORT
      LAYER metal2 ;
      RECT 307.005 570.990 307.075 571.200 ;
    END
  END r0_rd_out[70]
  PIN r0_rd_out[71]
    DIRECTION OUTPUT ;
    USE SIGNAL ;
    SHAPE ABUTMENT ;
    PORT
      LAYER metal2 ;
      RECT 311.375 570.990 311.445 571.200 ;
    END
  END r0_rd_out[71]
  PIN r0_rd_out[72]
    DIRECTION OUTPUT ;
    USE SIGNAL ;
    SHAPE ABUTMENT ;
    PORT
      LAYER metal2 ;
      RECT 315.745 570.990 315.815 571.200 ;
    END
  END r0_rd_out[72]
  PIN r0_rd_out[73]
    DIRECTION OUTPUT ;
    USE SIGNAL ;
    SHAPE ABUTMENT ;
    PORT
      LAYER metal2 ;
      RECT 320.115 570.990 320.185 571.200 ;
    END
  END r0_rd_out[73]
  PIN r0_rd_out[74]
    DIRECTION OUTPUT ;
    USE SIGNAL ;
    SHAPE ABUTMENT ;
    PORT
      LAYER metal2 ;
      RECT 324.485 570.990 324.555 571.200 ;
    END
  END r0_rd_out[74]
  PIN r0_rd_out[75]
    DIRECTION OUTPUT ;
    USE SIGNAL ;
    SHAPE ABUTMENT ;
    PORT
      LAYER metal2 ;
      RECT 328.855 570.990 328.925 571.200 ;
    END
  END r0_rd_out[75]
  PIN r0_rd_out[76]
    DIRECTION OUTPUT ;
    USE SIGNAL ;
    SHAPE ABUTMENT ;
    PORT
      LAYER metal2 ;
      RECT 333.225 570.990 333.295 571.200 ;
    END
  END r0_rd_out[76]
  PIN r0_rd_out[77]
    DIRECTION OUTPUT ;
    USE SIGNAL ;
    SHAPE ABUTMENT ;
    PORT
      LAYER metal2 ;
      RECT 337.595 570.990 337.665 571.200 ;
    END
  END r0_rd_out[77]
  PIN r0_rd_out[78]
    DIRECTION OUTPUT ;
    USE SIGNAL ;
    SHAPE ABUTMENT ;
    PORT
      LAYER metal2 ;
      RECT 341.965 570.990 342.035 571.200 ;
    END
  END r0_rd_out[78]
  PIN r0_rd_out[79]
    DIRECTION OUTPUT ;
    USE SIGNAL ;
    SHAPE ABUTMENT ;
    PORT
      LAYER metal2 ;
      RECT 346.335 570.990 346.405 571.200 ;
    END
  END r0_rd_out[79]
  PIN r0_rd_out[80]
    DIRECTION OUTPUT ;
    USE SIGNAL ;
    SHAPE ABUTMENT ;
    PORT
      LAYER metal2 ;
      RECT 350.705 570.990 350.775 571.200 ;
    END
  END r0_rd_out[80]
  PIN r0_rd_out[81]
    DIRECTION OUTPUT ;
    USE SIGNAL ;
    SHAPE ABUTMENT ;
    PORT
      LAYER metal2 ;
      RECT 355.075 570.990 355.145 571.200 ;
    END
  END r0_rd_out[81]
  PIN r0_rd_out[82]
    DIRECTION OUTPUT ;
    USE SIGNAL ;
    SHAPE ABUTMENT ;
    PORT
      LAYER metal2 ;
      RECT 359.445 570.990 359.515 571.200 ;
    END
  END r0_rd_out[82]
  PIN r0_rd_out[83]
    DIRECTION OUTPUT ;
    USE SIGNAL ;
    SHAPE ABUTMENT ;
    PORT
      LAYER metal2 ;
      RECT 363.815 570.990 363.885 571.200 ;
    END
  END r0_rd_out[83]
  PIN r0_rd_out[84]
    DIRECTION OUTPUT ;
    USE SIGNAL ;
    SHAPE ABUTMENT ;
    PORT
      LAYER metal2 ;
      RECT 368.185 570.990 368.255 571.200 ;
    END
  END r0_rd_out[84]
  PIN r0_rd_out[85]
    DIRECTION OUTPUT ;
    USE SIGNAL ;
    SHAPE ABUTMENT ;
    PORT
      LAYER metal2 ;
      RECT 372.555 570.990 372.625 571.200 ;
    END
  END r0_rd_out[85]
  PIN r0_rd_out[86]
    DIRECTION OUTPUT ;
    USE SIGNAL ;
    SHAPE ABUTMENT ;
    PORT
      LAYER metal2 ;
      RECT 376.925 570.990 376.995 571.200 ;
    END
  END r0_rd_out[86]
  PIN r0_rd_out[87]
    DIRECTION OUTPUT ;
    USE SIGNAL ;
    SHAPE ABUTMENT ;
    PORT
      LAYER metal2 ;
      RECT 381.295 570.990 381.365 571.200 ;
    END
  END r0_rd_out[87]
  PIN r0_rd_out[88]
    DIRECTION OUTPUT ;
    USE SIGNAL ;
    SHAPE ABUTMENT ;
    PORT
      LAYER metal2 ;
      RECT 385.665 570.990 385.735 571.200 ;
    END
  END r0_rd_out[88]
  PIN r0_rd_out[89]
    DIRECTION OUTPUT ;
    USE SIGNAL ;
    SHAPE ABUTMENT ;
    PORT
      LAYER metal2 ;
      RECT 390.035 570.990 390.105 571.200 ;
    END
  END r0_rd_out[89]
  PIN r0_rd_out[90]
    DIRECTION OUTPUT ;
    USE SIGNAL ;
    SHAPE ABUTMENT ;
    PORT
      LAYER metal2 ;
      RECT 394.405 570.990 394.475 571.200 ;
    END
  END r0_rd_out[90]
  PIN r0_rd_out[91]
    DIRECTION OUTPUT ;
    USE SIGNAL ;
    SHAPE ABUTMENT ;
    PORT
      LAYER metal2 ;
      RECT 398.775 570.990 398.845 571.200 ;
    END
  END r0_rd_out[91]
  PIN r0_rd_out[92]
    DIRECTION OUTPUT ;
    USE SIGNAL ;
    SHAPE ABUTMENT ;
    PORT
      LAYER metal2 ;
      RECT 403.145 570.990 403.215 571.200 ;
    END
  END r0_rd_out[92]
  PIN r0_rd_out[93]
    DIRECTION OUTPUT ;
    USE SIGNAL ;
    SHAPE ABUTMENT ;
    PORT
      LAYER metal2 ;
      RECT 407.515 570.990 407.585 571.200 ;
    END
  END r0_rd_out[93]
  PIN r0_rd_out[94]
    DIRECTION OUTPUT ;
    USE SIGNAL ;
    SHAPE ABUTMENT ;
    PORT
      LAYER metal2 ;
      RECT 411.885 570.990 411.955 571.200 ;
    END
  END r0_rd_out[94]
  PIN r0_rd_out[95]
    DIRECTION OUTPUT ;
    USE SIGNAL ;
    SHAPE ABUTMENT ;
    PORT
      LAYER metal2 ;
      RECT 416.255 570.990 416.325 571.200 ;
    END
  END r0_rd_out[95]
  PIN r0_rd_out[96]
    DIRECTION OUTPUT ;
    USE SIGNAL ;
    SHAPE ABUTMENT ;
    PORT
      LAYER metal2 ;
      RECT 420.625 570.990 420.695 571.200 ;
    END
  END r0_rd_out[96]
  PIN r0_rd_out[97]
    DIRECTION OUTPUT ;
    USE SIGNAL ;
    SHAPE ABUTMENT ;
    PORT
      LAYER metal2 ;
      RECT 424.995 570.990 425.065 571.200 ;
    END
  END r0_rd_out[97]
  PIN r0_rd_out[98]
    DIRECTION OUTPUT ;
    USE SIGNAL ;
    SHAPE ABUTMENT ;
    PORT
      LAYER metal2 ;
      RECT 429.365 570.990 429.435 571.200 ;
    END
  END r0_rd_out[98]
  PIN r0_rd_out[99]
    DIRECTION OUTPUT ;
    USE SIGNAL ;
    SHAPE ABUTMENT ;
    PORT
      LAYER metal2 ;
      RECT 433.735 570.990 433.805 571.200 ;
    END
  END r0_rd_out[99]
  PIN r0_rd_out[100]
    DIRECTION OUTPUT ;
    USE SIGNAL ;
    SHAPE ABUTMENT ;
    PORT
      LAYER metal2 ;
      RECT 438.105 570.990 438.175 571.200 ;
    END
  END r0_rd_out[100]
  PIN r0_rd_out[101]
    DIRECTION OUTPUT ;
    USE SIGNAL ;
    SHAPE ABUTMENT ;
    PORT
      LAYER metal2 ;
      RECT 442.475 570.990 442.545 571.200 ;
    END
  END r0_rd_out[101]
  PIN r0_rd_out[102]
    DIRECTION OUTPUT ;
    USE SIGNAL ;
    SHAPE ABUTMENT ;
    PORT
      LAYER metal2 ;
      RECT 446.845 570.990 446.915 571.200 ;
    END
  END r0_rd_out[102]
  PIN r0_rd_out[103]
    DIRECTION OUTPUT ;
    USE SIGNAL ;
    SHAPE ABUTMENT ;
    PORT
      LAYER metal2 ;
      RECT 451.215 570.990 451.285 571.200 ;
    END
  END r0_rd_out[103]
  PIN r0_rd_out[104]
    DIRECTION OUTPUT ;
    USE SIGNAL ;
    SHAPE ABUTMENT ;
    PORT
      LAYER metal2 ;
      RECT 455.585 570.990 455.655 571.200 ;
    END
  END r0_rd_out[104]
  PIN r0_rd_out[105]
    DIRECTION OUTPUT ;
    USE SIGNAL ;
    SHAPE ABUTMENT ;
    PORT
      LAYER metal2 ;
      RECT 459.955 570.990 460.025 571.200 ;
    END
  END r0_rd_out[105]
  PIN r0_rd_out[106]
    DIRECTION OUTPUT ;
    USE SIGNAL ;
    SHAPE ABUTMENT ;
    PORT
      LAYER metal2 ;
      RECT 464.325 570.990 464.395 571.200 ;
    END
  END r0_rd_out[106]
  PIN r0_rd_out[107]
    DIRECTION OUTPUT ;
    USE SIGNAL ;
    SHAPE ABUTMENT ;
    PORT
      LAYER metal2 ;
      RECT 468.695 570.990 468.765 571.200 ;
    END
  END r0_rd_out[107]
  PIN r0_rd_out[108]
    DIRECTION OUTPUT ;
    USE SIGNAL ;
    SHAPE ABUTMENT ;
    PORT
      LAYER metal2 ;
      RECT 473.065 570.990 473.135 571.200 ;
    END
  END r0_rd_out[108]
  PIN r0_rd_out[109]
    DIRECTION OUTPUT ;
    USE SIGNAL ;
    SHAPE ABUTMENT ;
    PORT
      LAYER metal2 ;
      RECT 477.435 570.990 477.505 571.200 ;
    END
  END r0_rd_out[109]
  PIN r0_rd_out[110]
    DIRECTION OUTPUT ;
    USE SIGNAL ;
    SHAPE ABUTMENT ;
    PORT
      LAYER metal2 ;
      RECT 481.805 570.990 481.875 571.200 ;
    END
  END r0_rd_out[110]
  PIN r0_rd_out[111]
    DIRECTION OUTPUT ;
    USE SIGNAL ;
    SHAPE ABUTMENT ;
    PORT
      LAYER metal2 ;
      RECT 486.175 570.990 486.245 571.200 ;
    END
  END r0_rd_out[111]
  PIN r0_rd_out[112]
    DIRECTION OUTPUT ;
    USE SIGNAL ;
    SHAPE ABUTMENT ;
    PORT
      LAYER metal2 ;
      RECT 490.545 570.990 490.615 571.200 ;
    END
  END r0_rd_out[112]
  PIN r0_rd_out[113]
    DIRECTION OUTPUT ;
    USE SIGNAL ;
    SHAPE ABUTMENT ;
    PORT
      LAYER metal2 ;
      RECT 494.915 570.990 494.985 571.200 ;
    END
  END r0_rd_out[113]
  PIN r0_rd_out[114]
    DIRECTION OUTPUT ;
    USE SIGNAL ;
    SHAPE ABUTMENT ;
    PORT
      LAYER metal2 ;
      RECT 499.285 570.990 499.355 571.200 ;
    END
  END r0_rd_out[114]
  PIN r0_rd_out[115]
    DIRECTION OUTPUT ;
    USE SIGNAL ;
    SHAPE ABUTMENT ;
    PORT
      LAYER metal2 ;
      RECT 503.655 570.990 503.725 571.200 ;
    END
  END r0_rd_out[115]
  PIN r0_rd_out[116]
    DIRECTION OUTPUT ;
    USE SIGNAL ;
    SHAPE ABUTMENT ;
    PORT
      LAYER metal2 ;
      RECT 508.025 570.990 508.095 571.200 ;
    END
  END r0_rd_out[116]
  PIN r0_rd_out[117]
    DIRECTION OUTPUT ;
    USE SIGNAL ;
    SHAPE ABUTMENT ;
    PORT
      LAYER metal2 ;
      RECT 512.395 570.990 512.465 571.200 ;
    END
  END r0_rd_out[117]
  PIN r0_rd_out[118]
    DIRECTION OUTPUT ;
    USE SIGNAL ;
    SHAPE ABUTMENT ;
    PORT
      LAYER metal2 ;
      RECT 516.765 570.990 516.835 571.200 ;
    END
  END r0_rd_out[118]
  PIN r0_rd_out[119]
    DIRECTION OUTPUT ;
    USE SIGNAL ;
    SHAPE ABUTMENT ;
    PORT
      LAYER metal2 ;
      RECT 521.135 570.990 521.205 571.200 ;
    END
  END r0_rd_out[119]
  PIN r0_rd_out[120]
    DIRECTION OUTPUT ;
    USE SIGNAL ;
    SHAPE ABUTMENT ;
    PORT
      LAYER metal2 ;
      RECT 525.505 570.990 525.575 571.200 ;
    END
  END r0_rd_out[120]
  PIN r0_rd_out[121]
    DIRECTION OUTPUT ;
    USE SIGNAL ;
    SHAPE ABUTMENT ;
    PORT
      LAYER metal2 ;
      RECT 529.875 570.990 529.945 571.200 ;
    END
  END r0_rd_out[121]
  PIN r0_rd_out[122]
    DIRECTION OUTPUT ;
    USE SIGNAL ;
    SHAPE ABUTMENT ;
    PORT
      LAYER metal2 ;
      RECT 534.245 570.990 534.315 571.200 ;
    END
  END r0_rd_out[122]
  PIN r0_rd_out[123]
    DIRECTION OUTPUT ;
    USE SIGNAL ;
    SHAPE ABUTMENT ;
    PORT
      LAYER metal2 ;
      RECT 538.615 570.990 538.685 571.200 ;
    END
  END r0_rd_out[123]
  PIN r0_rd_out[124]
    DIRECTION OUTPUT ;
    USE SIGNAL ;
    SHAPE ABUTMENT ;
    PORT
      LAYER metal2 ;
      RECT 542.985 570.990 543.055 571.200 ;
    END
  END r0_rd_out[124]
  PIN r0_rd_out[125]
    DIRECTION OUTPUT ;
    USE SIGNAL ;
    SHAPE ABUTMENT ;
    PORT
      LAYER metal2 ;
      RECT 547.355 570.990 547.425 571.200 ;
    END
  END r0_rd_out[125]
  PIN r0_rd_out[126]
    DIRECTION OUTPUT ;
    USE SIGNAL ;
    SHAPE ABUTMENT ;
    PORT
      LAYER metal2 ;
      RECT 551.725 570.990 551.795 571.200 ;
    END
  END r0_rd_out[126]
  PIN r0_rd_out[127]
    DIRECTION OUTPUT ;
    USE SIGNAL ;
    SHAPE ABUTMENT ;
    PORT
      LAYER metal2 ;
      RECT 556.095 570.990 556.165 571.200 ;
    END
  END r0_rd_out[127]
  PIN r0_rd_out[128]
    DIRECTION OUTPUT ;
    USE SIGNAL ;
    SHAPE ABUTMENT ;
    PORT
      LAYER metal2 ;
      RECT 560.465 570.990 560.535 571.200 ;
    END
  END r0_rd_out[128]
  PIN r0_rd_out[129]
    DIRECTION OUTPUT ;
    USE SIGNAL ;
    SHAPE ABUTMENT ;
    PORT
      LAYER metal2 ;
      RECT 564.835 570.990 564.905 571.200 ;
    END
  END r0_rd_out[129]
  PIN rw0_addr_in[0]
    DIRECTION INPUT ;
    USE SIGNAL ;
    SHAPE ABUTMENT ;
    PORT
      LAYER metal3 ;
      RECT 0.000 435.085 0.210 435.155 ;
    END
  END rw0_addr_in[0]
  PIN rw0_addr_in[1]
    DIRECTION INPUT ;
    USE SIGNAL ;
    SHAPE ABUTMENT ;
    PORT
      LAYER metal3 ;
      RECT 0.000 448.245 0.210 448.315 ;
    END
  END rw0_addr_in[1]
  PIN rw0_addr_in[2]
    DIRECTION INPUT ;
    USE SIGNAL ;
    SHAPE ABUTMENT ;
    PORT
      LAYER metal3 ;
      RECT 0.000 461.405 0.210 461.475 ;
    END
  END rw0_addr_in[2]
  PIN rw0_addr_in[3]
    DIRECTION INPUT ;
    USE SIGNAL ;
    SHAPE ABUTMENT ;
    PORT
      LAYER metal3 ;
      RECT 0.000 474.565 0.210 474.635 ;
    END
  END rw0_addr_in[3]
  PIN rw0_addr_in[4]
    DIRECTION INPUT ;
    USE SIGNAL ;
    SHAPE ABUTMENT ;
    PORT
      LAYER metal3 ;
      RECT 0.000 487.725 0.210 487.795 ;
    END
  END rw0_addr_in[4]
  PIN rw0_addr_in[5]
    DIRECTION INPUT ;
    USE SIGNAL ;
    SHAPE ABUTMENT ;
    PORT
      LAYER metal3 ;
      RECT 603.610 421.925 603.820 421.995 ;
    END
  END rw0_addr_in[5]
  PIN rw0_addr_in[6]
    DIRECTION INPUT ;
    USE SIGNAL ;
    SHAPE ABUTMENT ;
    PORT
      LAYER metal3 ;
      RECT 603.610 435.085 603.820 435.155 ;
    END
  END rw0_addr_in[6]
  PIN rw0_addr_in[7]
    DIRECTION INPUT ;
    USE SIGNAL ;
    SHAPE ABUTMENT ;
    PORT
      LAYER metal3 ;
      RECT 603.610 448.245 603.820 448.315 ;
    END
  END rw0_addr_in[7]
  PIN rw0_addr_in[8]
    DIRECTION INPUT ;
    USE SIGNAL ;
    SHAPE ABUTMENT ;
    PORT
      LAYER metal3 ;
      RECT 603.610 461.405 603.820 461.475 ;
    END
  END rw0_addr_in[8]
  PIN rw0_addr_in[9]
    DIRECTION INPUT ;
    USE SIGNAL ;
    SHAPE ABUTMENT ;
    PORT
      LAYER metal3 ;
      RECT 603.610 474.565 603.820 474.635 ;
    END
  END rw0_addr_in[9]
  PIN r0_addr_in[0]
    DIRECTION INPUT ;
    USE SIGNAL ;
    SHAPE ABUTMENT ;
    PORT
      LAYER metal3 ;
      RECT 0.000 500.885 0.210 500.955 ;
    END
  END r0_addr_in[0]
  PIN r0_addr_in[1]
    DIRECTION INPUT ;
    USE SIGNAL ;
    SHAPE ABUTMENT ;
    PORT
      LAYER metal3 ;
      RECT 0.000 514.045 0.210 514.115 ;
    END
  END r0_addr_in[1]
  PIN r0_addr_in[2]
    DIRECTION INPUT ;
    USE SIGNAL ;
    SHAPE ABUTMENT ;
    PORT
      LAYER metal3 ;
      RECT 0.000 527.205 0.210 527.275 ;
    END
  END r0_addr_in[2]
  PIN r0_addr_in[3]
    DIRECTION INPUT ;
    USE SIGNAL ;
    SHAPE ABUTMENT ;
    PORT
      LAYER metal3 ;
      RECT 0.000 540.365 0.210 540.435 ;
    END
  END r0_addr_in[3]
  PIN r0_addr_in[4]
    DIRECTION INPUT ;
    USE SIGNAL ;
    SHAPE ABUTMENT ;
    PORT
      LAYER metal3 ;
      RECT 0.000 553.525 0.210 553.595 ;
    END
  END r0_addr_in[4]
  PIN r0_addr_in[5]
    DIRECTION INPUT ;
    USE SIGNAL ;
    SHAPE ABUTMENT ;
    PORT
      LAYER metal3 ;
      RECT 603.610 487.725 603.820 487.795 ;
    END
  END r0_addr_in[5]
  PIN r0_addr_in[6]
    DIRECTION INPUT ;
    USE SIGNAL ;
    SHAPE ABUTMENT ;
    PORT
      LAYER metal3 ;
      RECT 603.610 500.885 603.820 500.955 ;
    END
  END r0_addr_in[6]
  PIN r0_addr_in[7]
    DIRECTION INPUT ;
    USE SIGNAL ;
    SHAPE ABUTMENT ;
    PORT
      LAYER metal3 ;
      RECT 603.610 514.045 603.820 514.115 ;
    END
  END r0_addr_in[7]
  PIN r0_addr_in[8]
    DIRECTION INPUT ;
    USE SIGNAL ;
    SHAPE ABUTMENT ;
    PORT
      LAYER metal3 ;
      RECT 603.610 527.205 603.820 527.275 ;
    END
  END r0_addr_in[8]
  PIN r0_addr_in[9]
    DIRECTION INPUT ;
    USE SIGNAL ;
    SHAPE ABUTMENT ;
    PORT
      LAYER metal3 ;
      RECT 603.610 540.365 603.820 540.435 ;
    END
  END r0_addr_in[9]
  PIN rw0_we_in
    DIRECTION INPUT ;
    USE SIGNAL ;
    SHAPE ABUTMENT ;
    PORT
      LAYER metal2 ;
      RECT 569.205 570.990 569.275 571.200 ;
    END
  END rw0_we_in
  PIN rw0_ce_in
    DIRECTION INPUT ;
    USE SIGNAL ;
    SHAPE ABUTMENT ;
    PORT
      LAYER metal2 ;
      RECT 573.575 570.990 573.645 571.200 ;
    END
  END rw0_ce_in
  PIN rw0_clk
    DIRECTION INPUT ;
    USE SIGNAL ;
    SHAPE ABUTMENT ;
    PORT
      LAYER metal2 ;
      RECT 577.945 570.990 578.015 571.200 ;
    END
  END rw0_clk
  PIN r0_ce_in
    DIRECTION INPUT ;
    USE SIGNAL ;
    SHAPE ABUTMENT ;
    PORT
      LAYER metal2 ;
      RECT 582.315 570.990 582.385 571.200 ;
    END
  END r0_ce_in
  PIN r0_clk
    DIRECTION INPUT ;
    USE SIGNAL ;
    SHAPE ABUTMENT ;
    PORT
      LAYER metal2 ;
      RECT 586.685 570.990 586.755 571.200 ;
    END
  END r0_clk
  PIN VSS
    DIRECTION INOUT ;
    USE GROUND ;
    PORT
      LAYER metal4 ;
      RECT 1.000 0.840 1.280 570.360 ;
      RECT 3.240 0.840 3.520 570.360 ;
      RECT 5.480 0.840 5.760 570.360 ;
      RECT 7.720 0.840 8.000 570.360 ;
      RECT 9.960 0.840 10.240 570.360 ;
      RECT 12.200 0.840 12.480 570.360 ;
      RECT 14.440 0.840 14.720 570.360 ;
      RECT 16.680 0.840 16.960 570.360 ;
      RECT 18.920 0.840 19.200 570.360 ;
      RECT 21.160 0.840 21.440 570.360 ;
      RECT 23.400 0.840 23.680 570.360 ;
      RECT 25.640 0.840 25.920 570.360 ;
      RECT 27.880 0.840 28.160 570.360 ;
      RECT 30.120 0.840 30.400 570.360 ;
      RECT 32.360 0.840 32.640 570.360 ;
      RECT 34.600 0.840 34.880 570.360 ;
      RECT 36.840 0.840 37.120 570.360 ;
      RECT 39.080 0.840 39.360 570.360 ;
      RECT 41.320 0.840 41.600 570.360 ;
      RECT 43.560 0.840 43.840 570.360 ;
      RECT 45.800 0.840 46.080 570.360 ;
      RECT 48.040 0.840 48.320 570.360 ;
      RECT 50.280 0.840 50.560 570.360 ;
      RECT 52.520 0.840 52.800 570.360 ;
      RECT 54.760 0.840 55.040 570.360 ;
      RECT 57.000 0.840 57.280 570.360 ;
      RECT 59.240 0.840 59.520 570.360 ;
      RECT 61.480 0.840 61.760 570.360 ;
      RECT 63.720 0.840 64.000 570.360 ;
      RECT 65.960 0.840 66.240 570.360 ;
      RECT 68.200 0.840 68.480 570.360 ;
      RECT 70.440 0.840 70.720 570.360 ;
      RECT 72.680 0.840 72.960 570.360 ;
      RECT 74.920 0.840 75.200 570.360 ;
      RECT 77.160 0.840 77.440 570.360 ;
      RECT 79.400 0.840 79.680 570.360 ;
      RECT 81.640 0.840 81.920 570.360 ;
      RECT 83.880 0.840 84.160 570.360 ;
      RECT 86.120 0.840 86.400 570.360 ;
      RECT 88.360 0.840 88.640 570.360 ;
      RECT 90.600 0.840 90.880 570.360 ;
      RECT 92.840 0.840 93.120 570.360 ;
      RECT 95.080 0.840 95.360 570.360 ;
      RECT 97.320 0.840 97.600 570.360 ;
      RECT 99.560 0.840 99.840 570.360 ;
      RECT 101.800 0.840 102.080 570.360 ;
      RECT 104.040 0.840 104.320 570.360 ;
      RECT 106.280 0.840 106.560 570.360 ;
      RECT 108.520 0.840 108.800 570.360 ;
      RECT 110.760 0.840 111.040 570.360 ;
      RECT 113.000 0.840 113.280 570.360 ;
      RECT 115.240 0.840 115.520 570.360 ;
      RECT 117.480 0.840 117.760 570.360 ;
      RECT 119.720 0.840 120.000 570.360 ;
      RECT 121.960 0.840 122.240 570.360 ;
      RECT 124.200 0.840 124.480 570.360 ;
      RECT 126.440 0.840 126.720 570.360 ;
      RECT 128.680 0.840 128.960 570.360 ;
      RECT 130.920 0.840 131.200 570.360 ;
      RECT 133.160 0.840 133.440 570.360 ;
      RECT 135.400 0.840 135.680 570.360 ;
      RECT 137.640 0.840 137.920 570.360 ;
      RECT 139.880 0.840 140.160 570.360 ;
      RECT 142.120 0.840 142.400 570.360 ;
      RECT 144.360 0.840 144.640 570.360 ;
      RECT 146.600 0.840 146.880 570.360 ;
      RECT 148.840 0.840 149.120 570.360 ;
      RECT 151.080 0.840 151.360 570.360 ;
      RECT 153.320 0.840 153.600 570.360 ;
      RECT 155.560 0.840 155.840 570.360 ;
      RECT 157.800 0.840 158.080 570.360 ;
      RECT 160.040 0.840 160.320 570.360 ;
      RECT 162.280 0.840 162.560 570.360 ;
      RECT 164.520 0.840 164.800 570.360 ;
      RECT 166.760 0.840 167.040 570.360 ;
      RECT 169.000 0.840 169.280 570.360 ;
      RECT 171.240 0.840 171.520 570.360 ;
      RECT 173.480 0.840 173.760 570.360 ;
      RECT 175.720 0.840 176.000 570.360 ;
      RECT 177.960 0.840 178.240 570.360 ;
      RECT 180.200 0.840 180.480 570.360 ;
      RECT 182.440 0.840 182.720 570.360 ;
      RECT 184.680 0.840 184.960 570.360 ;
      RECT 186.920 0.840 187.200 570.360 ;
      RECT 189.160 0.840 189.440 570.360 ;
      RECT 191.400 0.840 191.680 570.360 ;
      RECT 193.640 0.840 193.920 570.360 ;
      RECT 195.880 0.840 196.160 570.360 ;
      RECT 198.120 0.840 198.400 570.360 ;
      RECT 200.360 0.840 200.640 570.360 ;
      RECT 202.600 0.840 202.880 570.360 ;
      RECT 204.840 0.840 205.120 570.360 ;
      RECT 207.080 0.840 207.360 570.360 ;
      RECT 209.320 0.840 209.600 570.360 ;
      RECT 211.560 0.840 211.840 570.360 ;
      RECT 213.800 0.840 214.080 570.360 ;
      RECT 216.040 0.840 216.320 570.360 ;
      RECT 218.280 0.840 218.560 570.360 ;
      RECT 220.520 0.840 220.800 570.360 ;
      RECT 222.760 0.840 223.040 570.360 ;
      RECT 225.000 0.840 225.280 570.360 ;
      RECT 227.240 0.840 227.520 570.360 ;
      RECT 229.480 0.840 229.760 570.360 ;
      RECT 231.720 0.840 232.000 570.360 ;
      RECT 233.960 0.840 234.240 570.360 ;
      RECT 236.200 0.840 236.480 570.360 ;
      RECT 238.440 0.840 238.720 570.360 ;
      RECT 240.680 0.840 240.960 570.360 ;
      RECT 242.920 0.840 243.200 570.360 ;
      RECT 245.160 0.840 245.440 570.360 ;
      RECT 247.400 0.840 247.680 570.360 ;
      RECT 249.640 0.840 249.920 570.360 ;
      RECT 251.880 0.840 252.160 570.360 ;
      RECT 254.120 0.840 254.400 570.360 ;
      RECT 256.360 0.840 256.640 570.360 ;
      RECT 258.600 0.840 258.880 570.360 ;
      RECT 260.840 0.840 261.120 570.360 ;
      RECT 263.080 0.840 263.360 570.360 ;
      RECT 265.320 0.840 265.600 570.360 ;
      RECT 267.560 0.840 267.840 570.360 ;
      RECT 269.800 0.840 270.080 570.360 ;
      RECT 272.040 0.840 272.320 570.360 ;
      RECT 274.280 0.840 274.560 570.360 ;
      RECT 276.520 0.840 276.800 570.360 ;
      RECT 278.760 0.840 279.040 570.360 ;
      RECT 281.000 0.840 281.280 570.360 ;
      RECT 283.240 0.840 283.520 570.360 ;
      RECT 285.480 0.840 285.760 570.360 ;
      RECT 287.720 0.840 288.000 570.360 ;
      RECT 289.960 0.840 290.240 570.360 ;
      RECT 292.200 0.840 292.480 570.360 ;
      RECT 294.440 0.840 294.720 570.360 ;
      RECT 296.680 0.840 296.960 570.360 ;
      RECT 298.920 0.840 299.200 570.360 ;
      RECT 301.160 0.840 301.440 570.360 ;
      RECT 303.400 0.840 303.680 570.360 ;
      RECT 305.640 0.840 305.920 570.360 ;
      RECT 307.880 0.840 308.160 570.360 ;
      RECT 310.120 0.840 310.400 570.360 ;
      RECT 312.360 0.840 312.640 570.360 ;
      RECT 314.600 0.840 314.880 570.360 ;
      RECT 316.840 0.840 317.120 570.360 ;
      RECT 319.080 0.840 319.360 570.360 ;
      RECT 321.320 0.840 321.600 570.360 ;
      RECT 323.560 0.840 323.840 570.360 ;
      RECT 325.800 0.840 326.080 570.360 ;
      RECT 328.040 0.840 328.320 570.360 ;
      RECT 330.280 0.840 330.560 570.360 ;
      RECT 332.520 0.840 332.800 570.360 ;
      RECT 334.760 0.840 335.040 570.360 ;
      RECT 337.000 0.840 337.280 570.360 ;
      RECT 339.240 0.840 339.520 570.360 ;
      RECT 341.480 0.840 341.760 570.360 ;
      RECT 343.720 0.840 344.000 570.360 ;
      RECT 345.960 0.840 346.240 570.360 ;
      RECT 348.200 0.840 348.480 570.360 ;
      RECT 350.440 0.840 350.720 570.360 ;
      RECT 352.680 0.840 352.960 570.360 ;
      RECT 354.920 0.840 355.200 570.360 ;
      RECT 357.160 0.840 357.440 570.360 ;
      RECT 359.400 0.840 359.680 570.360 ;
      RECT 361.640 0.840 361.920 570.360 ;
      RECT 363.880 0.840 364.160 570.360 ;
      RECT 366.120 0.840 366.400 570.360 ;
      RECT 368.360 0.840 368.640 570.360 ;
      RECT 370.600 0.840 370.880 570.360 ;
      RECT 372.840 0.840 373.120 570.360 ;
      RECT 375.080 0.840 375.360 570.360 ;
      RECT 377.320 0.840 377.600 570.360 ;
      RECT 379.560 0.840 379.840 570.360 ;
      RECT 381.800 0.840 382.080 570.360 ;
      RECT 384.040 0.840 384.320 570.360 ;
      RECT 386.280 0.840 386.560 570.360 ;
      RECT 388.520 0.840 388.800 570.360 ;
      RECT 390.760 0.840 391.040 570.360 ;
      RECT 393.000 0.840 393.280 570.360 ;
      RECT 395.240 0.840 395.520 570.360 ;
      RECT 397.480 0.840 397.760 570.360 ;
      RECT 399.720 0.840 400.000 570.360 ;
      RECT 401.960 0.840 402.240 570.360 ;
      RECT 404.200 0.840 404.480 570.360 ;
      RECT 406.440 0.840 406.720 570.360 ;
      RECT 408.680 0.840 408.960 570.360 ;
      RECT 410.920 0.840 411.200 570.360 ;
      RECT 413.160 0.840 413.440 570.360 ;
      RECT 415.400 0.840 415.680 570.360 ;
      RECT 417.640 0.840 417.920 570.360 ;
      RECT 419.880 0.840 420.160 570.360 ;
      RECT 422.120 0.840 422.400 570.360 ;
      RECT 424.360 0.840 424.640 570.360 ;
      RECT 426.600 0.840 426.880 570.360 ;
      RECT 428.840 0.840 429.120 570.360 ;
      RECT 431.080 0.840 431.360 570.360 ;
      RECT 433.320 0.840 433.600 570.360 ;
      RECT 435.560 0.840 435.840 570.360 ;
      RECT 437.800 0.840 438.080 570.360 ;
      RECT 440.040 0.840 440.320 570.360 ;
      RECT 442.280 0.840 442.560 570.360 ;
      RECT 444.520 0.840 444.800 570.360 ;
      RECT 446.760 0.840 447.040 570.360 ;
      RECT 449.000 0.840 449.280 570.360 ;
      RECT 451.240 0.840 451.520 570.360 ;
      RECT 453.480 0.840 453.760 570.360 ;
      RECT 455.720 0.840 456.000 570.360 ;
      RECT 457.960 0.840 458.240 570.360 ;
      RECT 460.200 0.840 460.480 570.360 ;
      RECT 462.440 0.840 462.720 570.360 ;
      RECT 464.680 0.840 464.960 570.360 ;
      RECT 466.920 0.840 467.200 570.360 ;
      RECT 469.160 0.840 469.440 570.360 ;
      RECT 471.400 0.840 471.680 570.360 ;
      RECT 473.640 0.840 473.920 570.360 ;
      RECT 475.880 0.840 476.160 570.360 ;
      RECT 478.120 0.840 478.400 570.360 ;
      RECT 480.360 0.840 480.640 570.360 ;
      RECT 482.600 0.840 482.880 570.360 ;
      RECT 484.840 0.840 485.120 570.360 ;
      RECT 487.080 0.840 487.360 570.360 ;
      RECT 489.320 0.840 489.600 570.360 ;
      RECT 491.560 0.840 491.840 570.360 ;
      RECT 493.800 0.840 494.080 570.360 ;
      RECT 496.040 0.840 496.320 570.360 ;
      RECT 498.280 0.840 498.560 570.360 ;
      RECT 500.520 0.840 500.800 570.360 ;
      RECT 502.760 0.840 503.040 570.360 ;
      RECT 505.000 0.840 505.280 570.360 ;
      RECT 507.240 0.840 507.520 570.360 ;
      RECT 509.480 0.840 509.760 570.360 ;
      RECT 511.720 0.840 512.000 570.360 ;
      RECT 513.960 0.840 514.240 570.360 ;
      RECT 516.200 0.840 516.480 570.360 ;
      RECT 518.440 0.840 518.720 570.360 ;
      RECT 520.680 0.840 520.960 570.360 ;
      RECT 522.920 0.840 523.200 570.360 ;
      RECT 525.160 0.840 525.440 570.360 ;
      RECT 527.400 0.840 527.680 570.360 ;
      RECT 529.640 0.840 529.920 570.360 ;
      RECT 531.880 0.840 532.160 570.360 ;
      RECT 534.120 0.840 534.400 570.360 ;
      RECT 536.360 0.840 536.640 570.360 ;
      RECT 538.600 0.840 538.880 570.360 ;
      RECT 540.840 0.840 541.120 570.360 ;
      RECT 543.080 0.840 543.360 570.360 ;
      RECT 545.320 0.840 545.600 570.360 ;
      RECT 547.560 0.840 547.840 570.360 ;
      RECT 549.800 0.840 550.080 570.360 ;
      RECT 552.040 0.840 552.320 570.360 ;
      RECT 554.280 0.840 554.560 570.360 ;
      RECT 556.520 0.840 556.800 570.360 ;
      RECT 558.760 0.840 559.040 570.360 ;
      RECT 561.000 0.840 561.280 570.360 ;
      RECT 563.240 0.840 563.520 570.360 ;
      RECT 565.480 0.840 565.760 570.360 ;
      RECT 567.720 0.840 568.000 570.360 ;
      RECT 569.960 0.840 570.240 570.360 ;
      RECT 572.200 0.840 572.480 570.360 ;
      RECT 574.440 0.840 574.720 570.360 ;
      RECT 576.680 0.840 576.960 570.360 ;
      RECT 578.920 0.840 579.200 570.360 ;
      RECT 581.160 0.840 581.440 570.360 ;
      RECT 583.400 0.840 583.680 570.360 ;
      RECT 585.640 0.840 585.920 570.360 ;
      RECT 587.880 0.840 588.160 570.360 ;
      RECT 590.120 0.840 590.400 570.360 ;
      RECT 592.360 0.840 592.640 570.360 ;
      RECT 594.600 0.840 594.880 570.360 ;
      RECT 596.840 0.840 597.120 570.360 ;
      RECT 599.080 0.840 599.360 570.360 ;
      RECT 601.320 0.840 601.600 570.360 ;
    END
  END VSS
  PIN VDD
    DIRECTION INOUT ;
    USE POWER ;
    PORT
      LAYER metal4 ;
      RECT 2.120 0.840 2.400 570.360 ;
      RECT 4.360 0.840 4.640 570.360 ;
      RECT 6.600 0.840 6.880 570.360 ;
      RECT 8.840 0.840 9.120 570.360 ;
      RECT 11.080 0.840 11.360 570.360 ;
      RECT 13.320 0.840 13.600 570.360 ;
      RECT 15.560 0.840 15.840 570.360 ;
      RECT 17.800 0.840 18.080 570.360 ;
      RECT 20.040 0.840 20.320 570.360 ;
      RECT 22.280 0.840 22.560 570.360 ;
      RECT 24.520 0.840 24.800 570.360 ;
      RECT 26.760 0.840 27.040 570.360 ;
      RECT 29.000 0.840 29.280 570.360 ;
      RECT 31.240 0.840 31.520 570.360 ;
      RECT 33.480 0.840 33.760 570.360 ;
      RECT 35.720 0.840 36.000 570.360 ;
      RECT 37.960 0.840 38.240 570.360 ;
      RECT 40.200 0.840 40.480 570.360 ;
      RECT 42.440 0.840 42.720 570.360 ;
      RECT 44.680 0.840 44.960 570.360 ;
      RECT 46.920 0.840 47.200 570.360 ;
      RECT 49.160 0.840 49.440 570.360 ;
      RECT 51.400 0.840 51.680 570.360 ;
      RECT 53.640 0.840 53.920 570.360 ;
      RECT 55.880 0.840 56.160 570.360 ;
      RECT 58.120 0.840 58.400 570.360 ;
      RECT 60.360 0.840 60.640 570.360 ;
      RECT 62.600 0.840 62.880 570.360 ;
      RECT 64.840 0.840 65.120 570.360 ;
      RECT 67.080 0.840 67.360 570.360 ;
      RECT 69.320 0.840 69.600 570.360 ;
      RECT 71.560 0.840 71.840 570.360 ;
      RECT 73.800 0.840 74.080 570.360 ;
      RECT 76.040 0.840 76.320 570.360 ;
      RECT 78.280 0.840 78.560 570.360 ;
      RECT 80.520 0.840 80.800 570.360 ;
      RECT 82.760 0.840 83.040 570.360 ;
      RECT 85.000 0.840 85.280 570.360 ;
      RECT 87.240 0.840 87.520 570.360 ;
      RECT 89.480 0.840 89.760 570.360 ;
      RECT 91.720 0.840 92.000 570.360 ;
      RECT 93.960 0.840 94.240 570.360 ;
      RECT 96.200 0.840 96.480 570.360 ;
      RECT 98.440 0.840 98.720 570.360 ;
      RECT 100.680 0.840 100.960 570.360 ;
      RECT 102.920 0.840 103.200 570.360 ;
      RECT 105.160 0.840 105.440 570.360 ;
      RECT 107.400 0.840 107.680 570.360 ;
      RECT 109.640 0.840 109.920 570.360 ;
      RECT 111.880 0.840 112.160 570.360 ;
      RECT 114.120 0.840 114.400 570.360 ;
      RECT 116.360 0.840 116.640 570.360 ;
      RECT 118.600 0.840 118.880 570.360 ;
      RECT 120.840 0.840 121.120 570.360 ;
      RECT 123.080 0.840 123.360 570.360 ;
      RECT 125.320 0.840 125.600 570.360 ;
      RECT 127.560 0.840 127.840 570.360 ;
      RECT 129.800 0.840 130.080 570.360 ;
      RECT 132.040 0.840 132.320 570.360 ;
      RECT 134.280 0.840 134.560 570.360 ;
      RECT 136.520 0.840 136.800 570.360 ;
      RECT 138.760 0.840 139.040 570.360 ;
      RECT 141.000 0.840 141.280 570.360 ;
      RECT 143.240 0.840 143.520 570.360 ;
      RECT 145.480 0.840 145.760 570.360 ;
      RECT 147.720 0.840 148.000 570.360 ;
      RECT 149.960 0.840 150.240 570.360 ;
      RECT 152.200 0.840 152.480 570.360 ;
      RECT 154.440 0.840 154.720 570.360 ;
      RECT 156.680 0.840 156.960 570.360 ;
      RECT 158.920 0.840 159.200 570.360 ;
      RECT 161.160 0.840 161.440 570.360 ;
      RECT 163.400 0.840 163.680 570.360 ;
      RECT 165.640 0.840 165.920 570.360 ;
      RECT 167.880 0.840 168.160 570.360 ;
      RECT 170.120 0.840 170.400 570.360 ;
      RECT 172.360 0.840 172.640 570.360 ;
      RECT 174.600 0.840 174.880 570.360 ;
      RECT 176.840 0.840 177.120 570.360 ;
      RECT 179.080 0.840 179.360 570.360 ;
      RECT 181.320 0.840 181.600 570.360 ;
      RECT 183.560 0.840 183.840 570.360 ;
      RECT 185.800 0.840 186.080 570.360 ;
      RECT 188.040 0.840 188.320 570.360 ;
      RECT 190.280 0.840 190.560 570.360 ;
      RECT 192.520 0.840 192.800 570.360 ;
      RECT 194.760 0.840 195.040 570.360 ;
      RECT 197.000 0.840 197.280 570.360 ;
      RECT 199.240 0.840 199.520 570.360 ;
      RECT 201.480 0.840 201.760 570.360 ;
      RECT 203.720 0.840 204.000 570.360 ;
      RECT 205.960 0.840 206.240 570.360 ;
      RECT 208.200 0.840 208.480 570.360 ;
      RECT 210.440 0.840 210.720 570.360 ;
      RECT 212.680 0.840 212.960 570.360 ;
      RECT 214.920 0.840 215.200 570.360 ;
      RECT 217.160 0.840 217.440 570.360 ;
      RECT 219.400 0.840 219.680 570.360 ;
      RECT 221.640 0.840 221.920 570.360 ;
      RECT 223.880 0.840 224.160 570.360 ;
      RECT 226.120 0.840 226.400 570.360 ;
      RECT 228.360 0.840 228.640 570.360 ;
      RECT 230.600 0.840 230.880 570.360 ;
      RECT 232.840 0.840 233.120 570.360 ;
      RECT 235.080 0.840 235.360 570.360 ;
      RECT 237.320 0.840 237.600 570.360 ;
      RECT 239.560 0.840 239.840 570.360 ;
      RECT 241.800 0.840 242.080 570.360 ;
      RECT 244.040 0.840 244.320 570.360 ;
      RECT 246.280 0.840 246.560 570.360 ;
      RECT 248.520 0.840 248.800 570.360 ;
      RECT 250.760 0.840 251.040 570.360 ;
      RECT 253.000 0.840 253.280 570.360 ;
      RECT 255.240 0.840 255.520 570.360 ;
      RECT 257.480 0.840 257.760 570.360 ;
      RECT 259.720 0.840 260.000 570.360 ;
      RECT 261.960 0.840 262.240 570.360 ;
      RECT 264.200 0.840 264.480 570.360 ;
      RECT 266.440 0.840 266.720 570.360 ;
      RECT 268.680 0.840 268.960 570.360 ;
      RECT 270.920 0.840 271.200 570.360 ;
      RECT 273.160 0.840 273.440 570.360 ;
      RECT 275.400 0.840 275.680 570.360 ;
      RECT 277.640 0.840 277.920 570.360 ;
      RECT 279.880 0.840 280.160 570.360 ;
      RECT 282.120 0.840 282.400 570.360 ;
      RECT 284.360 0.840 284.640 570.360 ;
      RECT 286.600 0.840 286.880 570.360 ;
      RECT 288.840 0.840 289.120 570.360 ;
      RECT 291.080 0.840 291.360 570.360 ;
      RECT 293.320 0.840 293.600 570.360 ;
      RECT 295.560 0.840 295.840 570.360 ;
      RECT 297.800 0.840 298.080 570.360 ;
      RECT 300.040 0.840 300.320 570.360 ;
      RECT 302.280 0.840 302.560 570.360 ;
      RECT 304.520 0.840 304.800 570.360 ;
      RECT 306.760 0.840 307.040 570.360 ;
      RECT 309.000 0.840 309.280 570.360 ;
      RECT 311.240 0.840 311.520 570.360 ;
      RECT 313.480 0.840 313.760 570.360 ;
      RECT 315.720 0.840 316.000 570.360 ;
      RECT 317.960 0.840 318.240 570.360 ;
      RECT 320.200 0.840 320.480 570.360 ;
      RECT 322.440 0.840 322.720 570.360 ;
      RECT 324.680 0.840 324.960 570.360 ;
      RECT 326.920 0.840 327.200 570.360 ;
      RECT 329.160 0.840 329.440 570.360 ;
      RECT 331.400 0.840 331.680 570.360 ;
      RECT 333.640 0.840 333.920 570.360 ;
      RECT 335.880 0.840 336.160 570.360 ;
      RECT 338.120 0.840 338.400 570.360 ;
      RECT 340.360 0.840 340.640 570.360 ;
      RECT 342.600 0.840 342.880 570.360 ;
      RECT 344.840 0.840 345.120 570.360 ;
      RECT 347.080 0.840 347.360 570.360 ;
      RECT 349.320 0.840 349.600 570.360 ;
      RECT 351.560 0.840 351.840 570.360 ;
      RECT 353.800 0.840 354.080 570.360 ;
      RECT 356.040 0.840 356.320 570.360 ;
      RECT 358.280 0.840 358.560 570.360 ;
      RECT 360.520 0.840 360.800 570.360 ;
      RECT 362.760 0.840 363.040 570.360 ;
      RECT 365.000 0.840 365.280 570.360 ;
      RECT 367.240 0.840 367.520 570.360 ;
      RECT 369.480 0.840 369.760 570.360 ;
      RECT 371.720 0.840 372.000 570.360 ;
      RECT 373.960 0.840 374.240 570.360 ;
      RECT 376.200 0.840 376.480 570.360 ;
      RECT 378.440 0.840 378.720 570.360 ;
      RECT 380.680 0.840 380.960 570.360 ;
      RECT 382.920 0.840 383.200 570.360 ;
      RECT 385.160 0.840 385.440 570.360 ;
      RECT 387.400 0.840 387.680 570.360 ;
      RECT 389.640 0.840 389.920 570.360 ;
      RECT 391.880 0.840 392.160 570.360 ;
      RECT 394.120 0.840 394.400 570.360 ;
      RECT 396.360 0.840 396.640 570.360 ;
      RECT 398.600 0.840 398.880 570.360 ;
      RECT 400.840 0.840 401.120 570.360 ;
      RECT 403.080 0.840 403.360 570.360 ;
      RECT 405.320 0.840 405.600 570.360 ;
      RECT 407.560 0.840 407.840 570.360 ;
      RECT 409.800 0.840 410.080 570.360 ;
      RECT 412.040 0.840 412.320 570.360 ;
      RECT 414.280 0.840 414.560 570.360 ;
      RECT 416.520 0.840 416.800 570.360 ;
      RECT 418.760 0.840 419.040 570.360 ;
      RECT 421.000 0.840 421.280 570.360 ;
      RECT 423.240 0.840 423.520 570.360 ;
      RECT 425.480 0.840 425.760 570.360 ;
      RECT 427.720 0.840 428.000 570.360 ;
      RECT 429.960 0.840 430.240 570.360 ;
      RECT 432.200 0.840 432.480 570.360 ;
      RECT 434.440 0.840 434.720 570.360 ;
      RECT 436.680 0.840 436.960 570.360 ;
      RECT 438.920 0.840 439.200 570.360 ;
      RECT 441.160 0.840 441.440 570.360 ;
      RECT 443.400 0.840 443.680 570.360 ;
      RECT 445.640 0.840 445.920 570.360 ;
      RECT 447.880 0.840 448.160 570.360 ;
      RECT 450.120 0.840 450.400 570.360 ;
      RECT 452.360 0.840 452.640 570.360 ;
      RECT 454.600 0.840 454.880 570.360 ;
      RECT 456.840 0.840 457.120 570.360 ;
      RECT 459.080 0.840 459.360 570.360 ;
      RECT 461.320 0.840 461.600 570.360 ;
      RECT 463.560 0.840 463.840 570.360 ;
      RECT 465.800 0.840 466.080 570.360 ;
      RECT 468.040 0.840 468.320 570.360 ;
      RECT 470.280 0.840 470.560 570.360 ;
      RECT 472.520 0.840 472.800 570.360 ;
      RECT 474.760 0.840 475.040 570.360 ;
      RECT 477.000 0.840 477.280 570.360 ;
      RECT 479.240 0.840 479.520 570.360 ;
      RECT 481.480 0.840 481.760 570.360 ;
      RECT 483.720 0.840 484.000 570.360 ;
      RECT 485.960 0.840 486.240 570.360 ;
      RECT 488.200 0.840 488.480 570.360 ;
      RECT 490.440 0.840 490.720 570.360 ;
      RECT 492.680 0.840 492.960 570.360 ;
      RECT 494.920 0.840 495.200 570.360 ;
      RECT 497.160 0.840 497.440 570.360 ;
      RECT 499.400 0.840 499.680 570.360 ;
      RECT 501.640 0.840 501.920 570.360 ;
      RECT 503.880 0.840 504.160 570.360 ;
      RECT 506.120 0.840 506.400 570.360 ;
      RECT 508.360 0.840 508.640 570.360 ;
      RECT 510.600 0.840 510.880 570.360 ;
      RECT 512.840 0.840 513.120 570.360 ;
      RECT 515.080 0.840 515.360 570.360 ;
      RECT 517.320 0.840 517.600 570.360 ;
      RECT 519.560 0.840 519.840 570.360 ;
      RECT 521.800 0.840 522.080 570.360 ;
      RECT 524.040 0.840 524.320 570.360 ;
      RECT 526.280 0.840 526.560 570.360 ;
      RECT 528.520 0.840 528.800 570.360 ;
      RECT 530.760 0.840 531.040 570.360 ;
      RECT 533.000 0.840 533.280 570.360 ;
      RECT 535.240 0.840 535.520 570.360 ;
      RECT 537.480 0.840 537.760 570.360 ;
      RECT 539.720 0.840 540.000 570.360 ;
      RECT 541.960 0.840 542.240 570.360 ;
      RECT 544.200 0.840 544.480 570.360 ;
      RECT 546.440 0.840 546.720 570.360 ;
      RECT 548.680 0.840 548.960 570.360 ;
      RECT 550.920 0.840 551.200 570.360 ;
      RECT 553.160 0.840 553.440 570.360 ;
      RECT 555.400 0.840 555.680 570.360 ;
      RECT 557.640 0.840 557.920 570.360 ;
      RECT 559.880 0.840 560.160 570.360 ;
      RECT 562.120 0.840 562.400 570.360 ;
      RECT 564.360 0.840 564.640 570.360 ;
      RECT 566.600 0.840 566.880 570.360 ;
      RECT 568.840 0.840 569.120 570.360 ;
      RECT 571.080 0.840 571.360 570.360 ;
      RECT 573.320 0.840 573.600 570.360 ;
      RECT 575.560 0.840 575.840 570.360 ;
      RECT 577.800 0.840 578.080 570.360 ;
      RECT 580.040 0.840 580.320 570.360 ;
      RECT 582.280 0.840 582.560 570.360 ;
      RECT 584.520 0.840 584.800 570.360 ;
      RECT 586.760 0.840 587.040 570.360 ;
      RECT 589.000 0.840 589.280 570.360 ;
      RECT 591.240 0.840 591.520 570.360 ;
      RECT 593.480 0.840 593.760 570.360 ;
      RECT 595.720 0.840 596.000 570.360 ;
      RECT 597.960 0.840 598.240 570.360 ;
      RECT 600.200 0.840 600.480 570.360 ;
      RECT 602.440 0.840 602.720 570.360 ;
    END
  END VDD
  OBS
    LAYER metal1 ;
    RECT 0 0 603.820 571.200 ;
    LAYER metal2 ;
    RECT 0 0 603.820 571.200 ;
    LAYER metal3 ;
    RECT 0 0 603.820 571.200 ;
    LAYER metal4 ;
    RECT 0 0 603.820 571.200 ;
    LAYER OVERLAP ;
    RECT 0 0 603.820 571.200 ;
  END
END fakeram_1rw1r_130w1024d_sram

END LIBRARY
